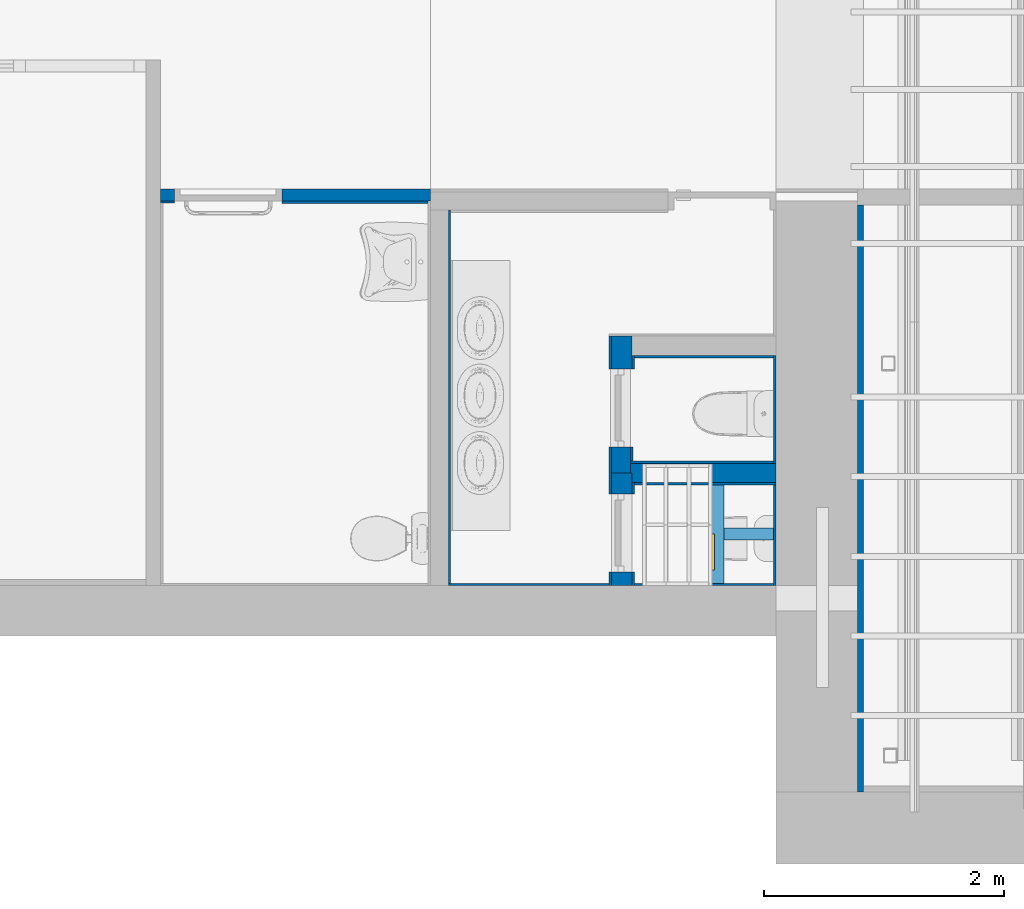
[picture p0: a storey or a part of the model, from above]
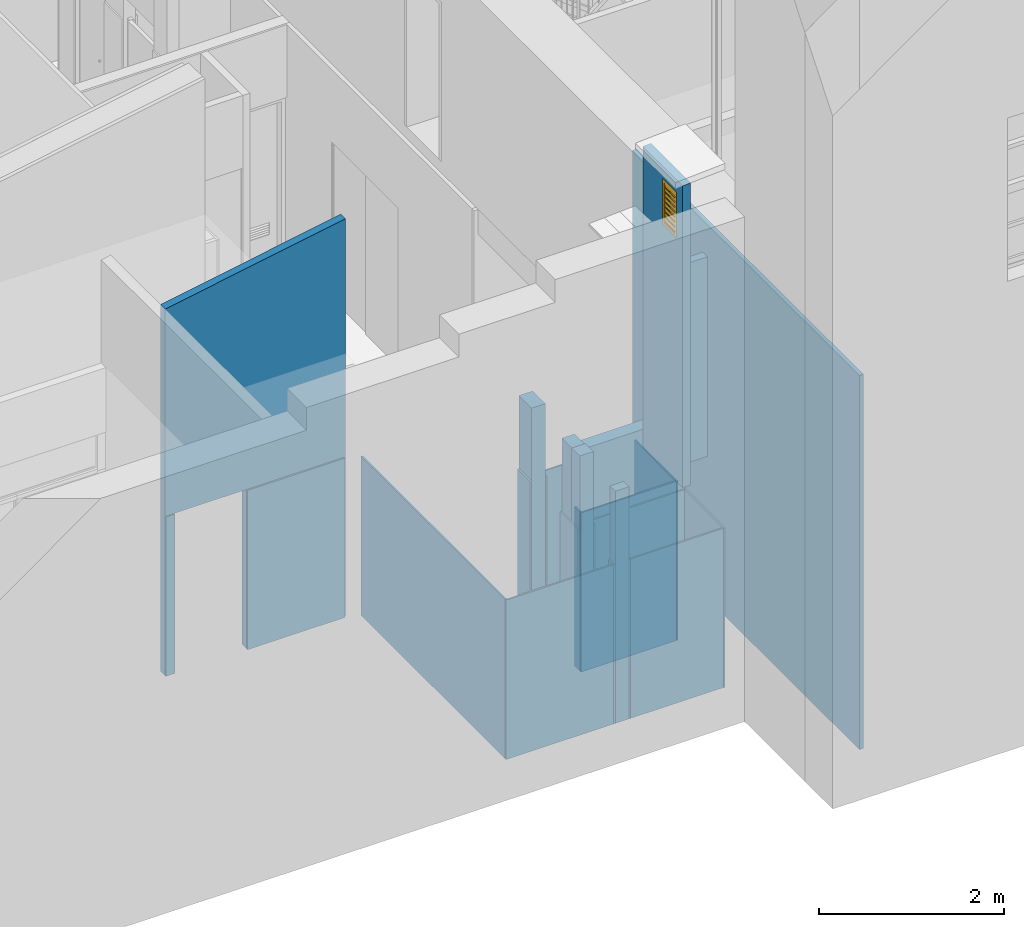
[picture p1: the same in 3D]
Properties of the parts of a building model (IFC2X3), part 1 of 2

# File
Description: ViewDefinition [CoordinationView_V2.0]
File name: 0001
Time: 2022-05-12T08:54:10
Written by: The EXPRESS Data Manager Version 5.02.0100.07 : 28 Aug 2013
Made in: 22.0.2.392 - Exporter 22.0.2.392 - IU alternativa 22.0.2.392
Comment: STEP Physical File produced by: The EXPRESS Data Manager Version 5.02.0100.07 : 28 Aug 2013 * Module: EDMstepFileFactory/EDMstandAlone * Creation date: Thu May 12 08:54:10 2022 * Host: DESKTOP-I1MM6I7 * Database: C:\Users\ALICIA~1\AppData\Local\Temp\2955ec9d-cea3-4671-8ac2-586a860548f9\22b83424-c5d4-4211-a013-65c01f56ca2a\ifc * Database version: 5507 * Database creation date: Thu May 12 08:53:25 2022 * Schema: IFC2X3 * Model: DataRepository.ifc * Model creation date: Thu May 12 08:53:25 2022 * Header model: DataRepository.ifc_HeaderModel * Header model creation date: Thu May 12 08:53:25 2022 * EDMuser: sdai-user * EDMgroup: sdai-group * License ID and type: 5605 : Permanent license. Expiry date: * EDMstepFileFactory options: 020000

# IfcProject, 0001
LongName: Nombre de proyecto; Phase: Estado de proyecto

# IfcSite, Superficie:1686468
RefLatitude: -34, -54, -17, -734680; RefLongitude: -56, -11, -31, -452026; RefElevation: 0 m

# IfcBuilding, Telegestiones
LongName: Telegestiones
Pset_AirSideSystemInformation - Description: LOCAL PARA TELEGESTIONES Local para Telegestiones - Centro
Pset_BuildingCommon - NumberOfStoreys: 4

# IfcBuildingStorey: Nivel:Extremo inicial Triangulo (4)
In: Telegestiones
Name | LongName | Elevation (m)
Nivel 0_NPT | Nivel 0_NPT | 0
Entrepiso_NPT | Entrepiso_NPT | 3.21
Nivel 1_NPT | Nivel 1_NPT | 4.94
Nivel 3_SUP | Nivel 3_SUP | 13.23

# IfcBeam: EST-PER-C-HGalv:C150X19.3 (10)
In: Nivel 0_NPT
Type - Pset_BeamCommon - IsExternal: no; LoadBearing: yes
Material: Metal - Acero - 345 MPa
Pset_BeamCommon - Slope: 0 deg; Reference: C150X19.3; Span: 19.49 m
Pset_QuantityTakeOff - Reference: C150X19.3; sets with these values: 2
Name (EST-PER-C-HGalv:C150X19.3:...)
1310847
1311190
1311201
1311212
1311223
1436319
1436321
1436323
1436325
1436327

# IfcBeam: EST-VI-PNI-Acero:EST-VI-IPN 140 (4)
In: Nivel 1_NPT
Type - Pset_BeamCommon - IsExternal: no; LoadBearing: yes
Material: Metal - Acero - 345 MPa
Pset_BeamCommon - Slope: 0 deg; Reference: EST-VI-IPN 140
Pset_QuantityTakeOff - Reference: EST-VI-IPN 140; sets with these values: 2
Name (EST-VI-PNI-Acero:EST-VI-IPN 140:...) | Span (m)
1302763 | 3.343
1389880 | 3.44
1452239 | 3.31
1452257 | 3.39

# IfcBeam: Hormigón-Viga rectangular:200x150 (2)
In: Entrepiso_NPT
Type - Pset_BeamCommon - IsExternal: no; LoadBearing: yes
Material: Hormigón, Moldeado in situ, gris
Pset_BeamCommon - Reference: 200x150; Span: 2.774 m; Slope: 10.384 deg
Pset_QuantityTakeOff - Reference: 200x150; sets with these values: 2
Name (Hormigón-Viga rectangular:200x150:...)
1787073
1787456

# IfcBeam: IPN - Secciones en I con alas cónicas:IPN 140 (2)
Type - PredefinedType: BEAM
Type - Pset_BeamCommon - IsExternal: no; LoadBearing: yes
Description: BP{BB9B63AE-4B4C-4E9F-9065-6A533A8D44FD}; Material: Metal - Acero - 345 MPa
Pset_BeamCommon - Slope: 0 deg; Reference: IPN 140
Pset_QuantityTakeOff - Reference: IPN 140; sets with these values: 2
ProfileProperties - SectionFamily: {BB9B63AE-4B4C-4E9F-9065-6A533A8D44FD}BP; Section: BP{BB9B63AE-4B4C-4E9F-9065-6A533A8D44FD}
Name (IPN - Secciones en I con alas cónicas:IPN 140:...) | In | Span (m)
1514774 | Nivel 0_NPT | 1.334
1530191 | Nivel 1_NPT | 1.253

# IfcBeam: IPN - Secciones en I con alas cónicas:IPN 140 (107)
Type - Pset_BeamCommon - IsExternal: no; LoadBearing: yes
Material: Metal - Acero - 345 MPa
Pset_BeamCommon - Reference: IPN 140
Pset_QuantityTakeOff - Reference: IPN 140; sets with these values: 2
Name (IPN - Secciones en I con alas cónicas:IPN 140:...) | In | Slope (deg) | Span (m)
1302759 | Nivel 1_NPT | 0 | 3.343
1302761 | Nivel 1_NPT | 0 | 3.49
1302765 | Nivel 1_NPT | 0 | 3.617
1302767 | Nivel 1_NPT | 0 | 3.617
1302769 | Nivel 1_NPT | 0 | 3.584
1387365 | Nivel 0_NPT | 0 | 0.7
1387483 | Nivel 1_NPT | 0 | 3.702
1388269 | Nivel 1_NPT | 0 | 3.586
1388583 | Nivel 1_NPT | 0 | 3.699
1389023 | Nivel 1_NPT | 0 | 3.699
1389478 | Nivel 1_NPT | 0 | 3.439
1391686 | Nivel 1_NPT | 0 | 3.69
1391717 | Nivel 1_NPT | 0 | 3.69
1391768 | Nivel 1_NPT | 0 | 3.69
1391782 | Nivel 1_NPT | 0 | 3.69
1391796 | Nivel 1_NPT | 0 | 3.69
1391810 | Nivel 1_NPT | 0 | 3.58
1391882 | Nivel 1_NPT | 0 | 3.58
1391896 | Nivel 1_NPT | 0 | 3.69
1391910 | Nivel 1_NPT | 0 | 3.69
1391924 | Nivel 1_NPT | 0 | 3.69
1391938 | Nivel 1_NPT | 0 | 3.69
1391952 | Nivel 1_NPT | 0 | 3.69
1392840 | Nivel 1_NPT | 0 | 3.48
1392855 | Nivel 1_NPT | 0 | 3.48
1392869 | Nivel 1_NPT | 0 | 3.48
1392887 | Nivel 1_NPT | 0 | 3.48
1392901 | Nivel 1_NPT | 0 | 3.48
1392915 | Nivel 1_NPT | 0 | 3.48
1392929 | Nivel 1_NPT | 0 | 3.48
1392943 | Nivel 1_NPT | 0 | 3.48
1392957 | Nivel 1_NPT | 0 | 3.48
1392971 | Nivel 1_NPT | 0 | 3.48
1392985 | Nivel 1_NPT | 0 | 3.48
1392999 | Nivel 1_NPT | 0 | 3.48
1452235 | Nivel 1_NPT | 0 | 3.31
1452237 | Nivel 1_NPT | 0 | 3.31
1452241 | Nivel 1_NPT | 0 | 3.31
1452243 | Nivel 1_NPT | 0 | 3.31
1452245 | Nivel 1_NPT | 0 | 3.31
1452247 | Nivel 1_NPT | 0 | 3.393
1452249 | Nivel 1_NPT | 0 | 3.39
1452251 | Nivel 1_NPT | 0 | 3.39
1452253 | Nivel 1_NPT | 0 | 3.39
1452255 | Nivel 1_NPT | 0 | 3.404
1452303 | Nivel 1_NPT | 0 | 3.39
1452305 | Nivel 1_NPT | 0 | 3.39
1452307 | Nivel 1_NPT | 0 | 3.39
1452309 | Nivel 1_NPT | 0 | 3.39
1452311 | Nivel 1_NPT | 0 | 3.39
1452313 | Nivel 1_NPT | 0 | 3.39
1452315 | Nivel 1_NPT | 0 | 3.39
1452317 | Nivel 1_NPT | 0 | 3.39
1452319 | Nivel 1_NPT | 0 | 3.39
1452321 | Nivel 1_NPT | 0 | 3.39
1452323 | Nivel 1_NPT | 0 | 3.39
1452325 | Nivel 1_NPT | 0 | 3.39
1452327 | Nivel 1_NPT | 0 | 3.31
1452329 | Nivel 1_NPT | 0 | 3.31
1452331 | Nivel 1_NPT | 0 | 3.31
1452333 | Nivel 1_NPT | 0 | 3.31
1452335 | Nivel 1_NPT | 0 | 3.31
1452337 | Nivel 1_NPT | 0 | 3.31
1452339 | Nivel 1_NPT | 0 | 3.31
1452341 | Nivel 1_NPT | 0 | 3.31
1452343 | Nivel 1_NPT | 0 | 3.31
1452345 | Nivel 1_NPT | 0 | 3.31
1452347 | Nivel 1_NPT | 0 | 3.31
1452349 | Nivel 1_NPT | 0 | 3.31
1466745 | Entrepiso_NPT | 0 | 1.26
1468459 | Entrepiso_NPT | 0 | 1.434
1469216 | Nivel 0_NPT | 0 | 1.334
1507818 | Nivel 0_NPT | 0 | 1.331
1514178 | Nivel 0_NPT | 37.3038 | 2.68
1514263 | Entrepiso_NPT | 0 | 1.218
1515129 | Entrepiso_NPT | 0 | 1.218
1515537 | Nivel 0_NPT | 0.0407811 | 1.217
1517027 | Nivel 0_NPT | 0.0000139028 | 1.218
1520294 | Entrepiso_NPT | 38.7536 | 2.65
1520296 | Entrepiso_NPT | 0 | 1.224
1520381 | Entrepiso_NPT | 0 | 1.42
1520383 | Entrepiso_NPT | 39.5917 | 2.593
1530181 | Nivel 1_NPT | 0 | 1.808
1567799 | Nivel 0_NPT | 0.00664997 | 1.334
1572878 | Nivel 1_NPT | 0 | 1.26
1572880 | Nivel 1_NPT | 0 | 1.334
1572882 | Nivel 1_NPT | 0 | 1.331
1572884 | Nivel 1_NPT | 35.1375 | 2.588
1572886 | Nivel 1_NPT | 0 | 1.218
1572888 | Nivel 1_NPT | 0.0515534 | 1.214
1572892 | Nivel 1_NPT | 0.0000139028 | 1.218
1572894 | Nivel 1_NPT | 36.6208 | 3.554
1572896 | Nivel 1_NPT | 0 | 1.224
1572898 | Nivel 1_NPT | 0 | 1.763
1572900 | Nivel 1_NPT | 37.8927 | 2.485
1572919 | Nivel 1_NPT | 0.00664997 | 1.334
1704734 | Nivel 1_NPT | 0 | 3.39
1704811 | Nivel 1_NPT | 0 | 3.39
1704841 | Nivel 1_NPT | 0 | 3.39
1704871 | Nivel 1_NPT | 0 | 3.39
1952851 | Nivel 1_NPT | 0.0000139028 | 1.218
1953647 | Nivel 0_NPT | 37.266 | 2.678
1954668 | Entrepiso_NPT | 39.5917 | 2.593
1955246 | Entrepiso_NPT | 38.7536 | 2.65
1955866 | Nivel 1_NPT | 35.1375 | 2.588
1956488 | Nivel 1_NPT | 36.6208 | 3.554
1956881 | Nivel 1_NPT | 37.8927 | 2.485

# IfcBeam: IPN - Secciones en I con alas cónicas:IPN 160 (14)
In: Nivel 3_SUP
Type - Pset_BeamCommon - IsExternal: no; LoadBearing: yes
Material: Metal - Acero - 345 MPa
Pset_BeamCommon - Reference: IPN 160
Pset_QuantityTakeOff - Reference: IPN 160; sets with these values: 2
Name (IPN - Secciones en I con alas cónicas:IPN 160:...) | Span (m) | Slope (deg)
1299421 | 19.549 | 0
1299466 | 19.607 | 0
1306593 | 8.92 | 0
1306595 | 4.777 | 29.4682
1432829 | 4.777 | 29.4682
1435526 | 8.92 | 0
1435528 | 4.777 | 29.4682
1435532 | 4.777 | 29.4682
1435557 | 8.92 | 0
1435559 | 4.777 | 29.4682
1435563 | 4.777 | 29.4682
1435588 | 8.92 | 0
1435590 | 4.777 | 29.4682
1435594 | 4.777 | 29.4682

# IfcBeam: IPN - Secciones en I con alas cónicas:IPN 200 (11)
In: Nivel 1_NPT
Type - Pset_BeamCommon - IsExternal: no; LoadBearing: yes
Material: Metal - Acero - 345 MPa
Pset_BeamCommon - Slope: 0 deg; Reference: IPN 200
Pset_QuantityTakeOff - Reference: IPN 200; sets with these values: 2
Name (IPN - Secciones en I con alas cónicas:IPN 200:...) | Span (m)
1302747 | 18.951
1302749 | 19.491
1302751 | 7.088
1302755 | 6.98
1302757 | 7.44
1386960 | 7.088
1452225 | 18.951
1452227 | 18.951
1452229 | 7.608
1452231 | 20.149
1452233 | 6.981

# IfcBeam: IPN - Secciones en I con alas cónicas:IPN 80 (94)
Type - Pset_BeamCommon - IsExternal: no; LoadBearing: yes
Material: Metal - Acero - 345 MPa
Pset_BeamCommon - Slope: 0 deg; Reference: IPN 80
Pset_QuantityTakeOff - Reference: IPN 80; sets with these values: 2
Name (IPN - Secciones en I con alas cónicas:IPN 80:...) | In | Span (m)
1390570 | Nivel 1_NPT | 1.616
1390802 | Nivel 1_NPT | 1.63
1390847 | Nivel 1_NPT | 1.63
1390906 | Nivel 1_NPT | 1.627
1391048 | Nivel 1_NPT | 1.616
1391101 | Nivel 1_NPT | 1.616
1391143 | Nivel 1_NPT | 1.63
1391172 | Nivel 1_NPT | 1.63
1391198 | Nivel 1_NPT | 1.63
1391265 | Nivel 1_NPT | 1.63
1391267 | Nivel 1_NPT | 1.63
1391269 | Nivel 1_NPT | 1.63
1391372 | Nivel 1_NPT | 1.63
1391374 | Nivel 1_NPT | 1.63
1391376 | Nivel 1_NPT | 1.63
1391414 | Nivel 1_NPT | 1.63
1391505 | Nivel 1_NPT | 1.63
1391507 | Nivel 1_NPT | 1.63
1391509 | Nivel 1_NPT | 1.63
1391581 | Nivel 1_NPT | 1.63
1391583 | Nivel 1_NPT | 1.63
1391585 | Nivel 1_NPT | 1.63
1452259 | Nivel 1_NPT | 1.616
1452261 | Nivel 1_NPT | 1.63
1452263 | Nivel 1_NPT | 1.63
1452265 | Nivel 1_NPT | 1.627
1452267 | Nivel 1_NPT | 1.63
1452269 | Nivel 1_NPT | 1.63
1452271 | Nivel 1_NPT | 1.63
1452273 | Nivel 1_NPT | 1.63
1452275 | Nivel 1_NPT | 1.63
1452277 | Nivel 1_NPT | 1.63
1452279 | Nivel 1_NPT | 1.63
1452281 | Nivel 1_NPT | 1.63
1452283 | Nivel 1_NPT | 1.63
1452285 | Nivel 1_NPT | 1.63
1452287 | Nivel 1_NPT | 1.63
1452289 | Nivel 1_NPT | 1.63
1452291 | Nivel 1_NPT | 1.63
1452293 | Nivel 1_NPT | 1.63
1452295 | Nivel 1_NPT | 1.63
1452297 | Nivel 1_NPT | 1.63
1452299 | Nivel 1_NPT | 1.63
1452301 | Nivel 1_NPT | 1.63
1880641 | Nivel 0_NPT | 3.86
1881168 | Nivel 0_NPT | 3.86
1881208 | Nivel 0_NPT | 3.86
1881211 | Nivel 0_NPT | 3.84
1881214 | Nivel 0_NPT | 3.86
1881288 | Nivel 0_NPT | 3.88
1881408 | Nivel 0_NPT | 3.86
1881443 | Nivel 0_NPT | 3.84
1881446 | Nivel 0_NPT | 3.86
1881449 | Nivel 0_NPT | 3.86
1881863 | Nivel 0_NPT | 4.44
1881866 | Nivel 0_NPT | 3.96
1881869 | Nivel 0_NPT | 3.955
1881872 | Nivel 0_NPT | 3.94
1881875 | Nivel 0_NPT | 3.96
1881878 | Nivel 0_NPT | 3.96
1881882 | Nivel 0_NPT | 3.96
1881885 | Nivel 0_NPT | 3.96
1881888 | Nivel 0_NPT | 3.96
1881891 | Nivel 0_NPT | 3.96
1882894 | Nivel 0_NPT | 3.902
1882897 | Nivel 0_NPT | 3.9
1882900 | Nivel 0_NPT | 3.907
1882903 | Nivel 0_NPT | 3.922
1882906 | Nivel 0_NPT | 3.902
1882909 | Nivel 0_NPT | 3.902
1882912 | Nivel 0_NPT | 3.902
1882915 | Nivel 0_NPT | 3.902
1882918 | Nivel 0_NPT | 3.902
1882921 | Nivel 0_NPT | 3.902
1882972 | Nivel 0_NPT | 4.097
1882975 | Nivel 0_NPT | 4.102
1882978 | Nivel 0_NPT | 4.1
1882981 | Nivel 0_NPT | 4.1
1882984 | Nivel 0_NPT | 4.1
1882987 | Nivel 0_NPT | 4.1
1882990 | Nivel 0_NPT | 4.1
1882993 | Nivel 0_NPT | 4.1
1882996 | Nivel 0_NPT | 4.1
1882999 | Nivel 0_NPT | 4.1
1883056 | Nivel 0_NPT | 4.095
1883059 | Nivel 0_NPT | 4.084
1883062 | Nivel 0_NPT | 4.084
1883065 | Nivel 0_NPT | 4.104
1883068 | Nivel 0_NPT | 4.084
1883071 | Nivel 0_NPT | 4.093
1883075 | Nivel 0_NPT | 4.084
1883078 | Nivel 0_NPT | 4.08
1883081 | Nivel 0_NPT | 4.084
1883084 | Nivel 0_NPT | 4.06

# IfcBeam: Madera:50x50mm (55)
Type - Pset_BeamCommon - IsExternal: no; LoadBearing: yes
Material: Madera - Madera de construcción
Pset_BeamCommon - Reference: 50x50mm
Pset_QuantityTakeOff - Reference: 50x50mm; sets with these values: 2
Name (Madera:50x50mm:...) | In | Span (m) | Slope (deg)
1884251 | Nivel 0_NPT | 5.14 | 29.4623
1884730 | Nivel 0_NPT | 5.14 | 29.4623
1884810 | Nivel 0_NPT | 5.14 | 29.4623
1884813 | Nivel 0_NPT | 5.14 | 29.4623
1884831 | Nivel 0_NPT | 5.14 | 29.4623
1884833 | Nivel 0_NPT | 5.14 | 29.4623
1884851 | Nivel 0_NPT | 5.14 | 29.4623
1884853 | Nivel 0_NPT | 5.14 | 29.4623
1884871 | Nivel 0_NPT | 5.14 | 29.4623
1884873 | Nivel 0_NPT | 5.14 | 29.4623
1885272 | Nivel 0_NPT | 5.14 | 29.4623
1885275 | Nivel 0_NPT | 5.14 | 29.4623
1885277 | Nivel 0_NPT | 5.14 | 29.4623
1885279 | Nivel 0_NPT | 5.14 | 29.4623
1885281 | Nivel 0_NPT | 5.14 | 29.4623
1885283 | Nivel 0_NPT | 5.14 | 29.4623
1885285 | Nivel 0_NPT | 5.14 | 29.4623
1885287 | Nivel 0_NPT | 5.14 | 29.4623
1885289 | Nivel 0_NPT | 5.14 | 29.4623
1885291 | Nivel 0_NPT | 5.14 | 29.4623
1885501 | Nivel 0_NPT | 5.14 | 29.4623
1885503 | Nivel 0_NPT | 5.14 | 29.4623
1885505 | Nivel 0_NPT | 5.14 | 29.4623
1885507 | Nivel 0_NPT | 5.14 | 29.4623
1885509 | Nivel 0_NPT | 5.14 | 29.4623
1885646 | Nivel 0_NPT | 5.14 | 29.4623
1885648 | Nivel 0_NPT | 5.14 | 29.4623
1885650 | Nivel 0_NPT | 5.14 | 29.4623
1885652 | Nivel 0_NPT | 5.14 | 29.4623
1885654 | Nivel 0_NPT | 5.14 | 29.4623
1885720 | Nivel 0_NPT | 5.14 | 29.4623
1885722 | Nivel 0_NPT | 5.14 | 29.4623
1885724 | Nivel 0_NPT | 5.14 | 29.4623
1885726 | Nivel 0_NPT | 5.14 | 29.4623
1885728 | Nivel 0_NPT | 5.14 | 29.4623
1885813 | Nivel 0_NPT | 5.14 | 29.4623
1885815 | Nivel 0_NPT | 5.14 | 29.4623
1885817 | Nivel 0_NPT | 5.14 | 29.4623
1885819 | Nivel 0_NPT | 5.14 | 29.4623
1885821 | Nivel 0_NPT | 5.14 | 29.4623
1885892 | Nivel 0_NPT | 5.14 | 29.4623
1885894 | Nivel 0_NPT | 5.14 | 29.4623
1885896 | Nivel 0_NPT | 5.14 | 29.4623
1885898 | Nivel 0_NPT | 5.14 | 29.4623
1885900 | Nivel 0_NPT | 5.14 | 29.4623
1885902 | Nivel 0_NPT | 5.14 | 29.4623
1885904 | Nivel 0_NPT | 5.14 | 29.4623
1885906 | Nivel 0_NPT | 5.14 | 29.4623
1885908 | Nivel 0_NPT | 5.14 | 29.4623
1885910 | Nivel 0_NPT | 5.14 | 29.4623
1886565 | Nivel 3_SUP | 3.955 | 0
1887055 | Nivel 3_SUP | 3.907 | 0
1887160 | Nivel 3_SUP | 3.888 | 0
1887330 | Nivel 3_SUP | 3.853 | 0
1887413 | Nivel 3_SUP | 4.113 | 0

# IfcBeam: U-Canales de ala paralela:UAP80 (10)
In: Nivel 0_NPT
Type - Pset_BeamCommon - IsExternal: no; LoadBearing: yes
Material: Metal - Acero - 345 MPa
Pset_BeamCommon - Slope: 0 deg; Reference: UAP80
Pset_QuantityTakeOff - Reference: UAP80; sets with these values: 2
Name (U-Canales de ala paralela:UAP80:...) | Span (m)
1764351 | 0.887
1766259 | 0.889
1766312 | 0.887
1766316 | 0.919
1766320 | 0.889
1766324 | 0.89
1766328 | 0.889
1766332 | 0.889
1766336 | 0.889
1773133 | 0.889

# IfcBeam: U-Canales de ala paralela:UPE160 (2)
In: Nivel 0_NPT
Type - Pset_BeamCommon - IsExternal: no; LoadBearing: yes
Material: Metal - Acero - 345 MPa
Pset_BeamCommon - Slope: 0 deg; Reference: UPE160
Pset_QuantityTakeOff - Reference: UPE160; sets with these values: 2
Name (U-Canales de ala paralela:UPE160:...) | Span (m)
1763657 | 9.61 | Pset_BeamCommon - IsExternal: yes
1763941 | 9.62

# IfcBuildingElementProxy: ARQ-ALE-EXT:Tipo 1, ARQ-ALE-EXT:Tipo 1:1745585
In: Entrepiso_NPT
Type - Material: <Unnamed>, Vidrio
Pset_BuildingElementProxyCommon - Reference: Tipo 1; sets with these values: 2

# IfcBuildingElementProxy: ARQ-BAR- Pasarela cubierta 2:ARQ-BAR- Pasarela cubierta 2, ARQ-BAR- Pasarela cubierta 2:ARQ-BAR- Pasarela cubierta 2:1774991
In: Nivel 3_SUP
Type - Material: <Unnamed> (16)
Pset_BuildingElementProxyCommon - Reference: ARQ-BAR- Pasarela cubierta 2; sets with these values: 2
Pset_ProvisionForVoid - Width: 8.81 m; Height: 0.05 m; Depth: 8.81 m

# IfcBuildingElementProxy: ARQ-BAR- Pasarela cubierta:ARQ-BAR- Pasarela cubierta, ARQ-BAR- Pasarela cubierta:ARQ-BAR- Pasarela cubierta:1775362
In: Nivel 3_SUP
Type - Material: <Unnamed> (16)
Pset_BuildingElementProxyCommon - Reference: ARQ-BAR- Pasarela cubierta; sets with these values: 2
Pset_ProvisionForVoid - Width: 9.61 m; Height: 0.05 m; Depth: 9.61 m

# IfcBuildingElementProxy: ARQ-ESC-EX-Ace-H3:Tipo 1 (2)
In: Nivel 3_SUP
Type - Material: <Unnamed>
Pset_BuildingElementProxyCommon - Reference: Tipo 1; sets with these values: 2
Name (ARQ-ESC-EX-Ace-H3:Tipo 1:...)
1776751
1776914

# IfcBuildingElementProxy: ARQ-ESC-EX-Ace:ARQ-ESC-EX-Ace, ARQ-ESC-EX-Ace:ARQ-ESC-EX-Ace:1759845
In: Nivel 1_NPT
Type - Material: <Unnamed>
Pset_BuildingElementProxyCommon - Reference: ARQ-ESC-EX-Ace; sets with these values: 2

# IfcBuildingElementProxy: ARQ-MU-EXT-Lad:Tipo 1 (12)
Type - Material: Albañilería expuesta (2)
Pset_BuildingElementProxyCommon - Reference: Tipo 1; sets with these values: 2
Pset_ProvisionForVoid - Height: 0.7 m
Name (ARQ-MU-EXT-Lad:Tipo 1:...) | In | Width (m) = Depth (m) | Material
1489611 | Nivel 3_SUP | 10.88
1491020 | Nivel 1_NPT | 10.88 | Albañilería expuesta
1491091 | Nivel 1_NPT | 10.88 | Albañilería expuesta
1491114 | Nivel 1_NPT | 10.88 | Albañilería expuesta
1491135 | Nivel 1_NPT | 10.88 | Albañilería expuesta
1491181 | Nivel 3_SUP | 10.88 | Albañilería expuesta
1492168 | Nivel 1_NPT | 9.7
1492191 | Nivel 1_NPT | 9.7 | Albañilería expuesta
1493948 | Nivel 3_SUP | 9.7 | Albañilería expuesta
1494081 | Nivel 1_NPT | 9.7 | Albañilería expuesta
1494138 | Nivel 1_NPT | 9.7 | Albañilería expuesta
1494168 | Nivel 1_NPT | 9.7 | Albañilería expuesta

# IfcBuildingElementProxy: ARQ-PAS-Osogrid-Ace:ARQ-PAS-Osogrid-Ace, ARQ-PAS-Osogrid-Ace:ARQ-PAS-Osogrid-Ace:1771462
In: Nivel 0_NPT
Type - Material: <Unnamed> (130)
Pset_BuildingElementProxyCommon - Reference: ARQ-PAS-Osogrid-Ace; sets with these values: 2
Pset_ProvisionForVoid - Width: 0.035 m; Height: 0.0025 m; Depth: 0.035 m

# IfcBuildingElementProxy: ARQ-Plataforma-Ace:ARQ-Plataforma-Ace, ARQ-Plataforma-Ace:ARQ-Plataforma-Ace:1753381
In: Nivel 1_NPT
Type - Material: <Unnamed>
Pset_BuildingElementProxyCommon - Reference: ARQ-Plataforma-Ace; sets with these values: 2

# IfcBuildingElementProxy: Armazón estructural 10:Armazón estructural 10, Armazón estructural 10:Armazón estructural 10:1543469
In: Entrepiso_NPT
Type - Material: Acero (10)
Pset_BuildingElementProxyCommon - Reference: Armazón estructural 10; sets with these values: 2
Pset_ProvisionForVoid - Width: 11.68 m; Depth: 11.68 m

# IfcBuildingElementProxy: Armazón estructural 1:Armazón estructural 1, Armazón estructural 1:Armazón estructural 1:1521064
In: Nivel 0_NPT
Type - Material: Metal-Acero
Pset_BuildingElementProxyCommon - Reference: Armazón estructural 1; sets with these values: 2
Pset_ProvisionForVoid - Width: 0.0564877 m; Height: 1.28479 m; Depth: 0.0564877 m

# IfcBuildingElementProxy: Armazón estructural 2:Armazón estructural 1, Armazón estructural 2:Armazón estructural 1:1572918
In: Nivel 1_NPT
Type - Material: Metal-Acero
Pset_BuildingElementProxyCommon - Reference: Armazón estructural 1; sets with these values: 2
Pset_ProvisionForVoid - Width: 0.0564877 m; Height: 1.28479 m; Depth: 0.0564877 m

# IfcBuildingElementProxy: Armazón estructural 5:Armazón estructural 3, Armazón estructural 5:Armazón estructural 3:1538624
In: Nivel 0_NPT
Type - Material: 391846a9_3117_44ae_832e_53e94a79c5b7 (2)
Pset_BuildingElementProxyCommon - Reference: Armazón estructural 3; sets with these values: 2
Pset_ProvisionForVoid - Width: 0.03 m; Depth: 0.03 m

# IfcBuildingElementProxy: Armazón estructural 6:Armazón estructural 3, Armazón estructural 6:Armazón estructural 3:1942421
In: Nivel 1_NPT
Type - Material: 391846a9_3117_44ae_832e_53e94a79c5b7 (4)
Pset_BuildingElementProxyCommon - Reference: Armazón estructural 3; sets with these values: 2
Pset_ProvisionForVoid - Width: 0.03 m; Depth: 0.03 m

# IfcBuildingElementProxy: Armazón estructural 7:Armazón estructural 7, Armazón estructural 7:Armazón estructural 7:1540061
In: Entrepiso_NPT
Type - Material: 391846a9_3117_44ae_832e_53e94a79c5b7 (2)
Pset_BuildingElementProxyCommon - Reference: Armazón estructural 7; sets with these values: 2
Pset_ProvisionForVoid - Width: 0.03 m; Depth: 0.03 m

# IfcBuildingElementProxy: Armazón estructural 8:Armazón estructural 7, Armazón estructural 8:Armazón estructural 7:1946343
In: Nivel 1_NPT
Type - Material: 391846a9_3117_44ae_832e_53e94a79c5b7 (2)
Pset_BuildingElementProxyCommon - Reference: Armazón estructural 7; sets with these values: 2
Pset_ProvisionForVoid - Width: 0.03 m; Depth: 0.03 m

# IfcBuildingElementProxy: Busto de Artigas:Busto de Artigas, Busto de Artigas:Busto de Artigas:1333514
In: Nivel 0_NPT
Type - Material: Hormigón, C12/15 (2)
Pset_BuildingElementProxyCommon - Reference: Busto de Artigas; sets with these values: 2
Pset_ProvisionForVoid - Width: 1.2 m; Height: 0.39 m; Depth: 1.2 m

# IfcBuildingElementProxy: Busto:Busto, Busto:Busto:1826441
In: Nivel 0_NPT
Type - Material: Acero (2)
Pset_BuildingElementProxyCommon - Reference: Busto; sets with these values: 2
Pset_ProvisionForVoid - Width: 0.05 m; Depth: 0.05 m

# IfcBuildingElementProxy: EST-PERF-Ace:EST-PERF-Ace (32)
In: Nivel 1_NPT
Type - Material: Metal-Acero
Pset_BuildingElementProxyCommon - Reference: EST-PERF-Ace; sets with these values: 2
Pset_ProvisionForVoid - Width: 0.01 m; Depth: 0.01 m
Name (EST-PERF-Ace:EST-PERF-Ace:...)
1717569
1718236
1718275
1718317
1718358
1718379
1718398
1718419
1718788
1718807
1718826
1718847
1718866
1718885
1718904
1718923
1718949
1721362
1721381
1721400
1721419
1721438
1721457
1721476
1721495
1721514
1721533
1721552
1721575
1721594
1721613
1721632

# IfcBuildingElementProxy: Perfiles escalera1:Perfiles escalera, Perfiles escalera1:Perfiles escalera:1573338
In: Nivel 1_NPT
Type - Material: Acero (2)
Pset_BuildingElementProxyCommon - Reference: Perfiles escalera; sets with these values: 2
Pset_ProvisionForVoid - Width: 0.03 m; Depth: 0.03 m

# IfcBuildingElementProxy: Perfiles escalera2:Perfiles escalera, Perfiles escalera2:Perfiles escalera:1957731
In: Nivel 0_NPT
Type - Material: Acero
Pset_BuildingElementProxyCommon - Reference: Perfiles escalera; sets with these values: 2
Pset_ProvisionForVoid - Width: 0.03 m; Depth: 0.03 m

# IfcBuildingElementProxy: Perfiles escalera:Perfiles escalera, Perfiles escalera:Perfiles escalera:1534310
In: Nivel 0_NPT
Type - Material: Acero
Pset_BuildingElementProxyCommon - Reference: Perfiles escalera; sets with these values: 2
Pset_ProvisionForVoid - Width: 0.03 m; Depth: 0.03 m

# IfcBuildingElementProxy: RPC Árbol - Otoño:Abedul gris - 3,1 metros (4)
In: Nivel 0_NPT
Type - Material: <Unnamed>
Pset_BuildingElementProxyCommon - Reference: Abedul gris - 3,1 metros; sets with these values: 2
Name (RPC Árbol - Otoño:Abedul gris - 3,1 metros:...)
1856726
1856905
1856915
1856923

# IfcBuildingElementProxy: RPC Árbol - Otoño:Acacia de tres púas - 7,6 metros, RPC Árbol - Otoño:Acacia de tres púas - 7,6 metros:1856717
In: Nivel 0_NPT
Type - Material: <Unnamed>
Pset_BuildingElementProxyCommon - Reference: Acacia de tres púas - 7,6 metros; sets with these values: 2

# IfcBuildingElementProxy: RPC Árbol - Otoño:Fresno blanco - 9,1 metros, RPC Árbol - Otoño:Fresno blanco - 9,1 metros:1829723
In: Nivel 0_NPT
Type - Material: <Unnamed>
Pset_BuildingElementProxyCommon - Reference: Fresno blanco - 9,1 metros; sets with these values: 2

# IfcBuildingElementProxy: RPC Árbol - Otoño:Haya americana - 6,0 metros, RPC Árbol - Otoño:Haya americana - 6,0 metros:1856966
In: Nivel 0_NPT
Type - Material: <Unnamed>
Pset_BuildingElementProxyCommon - Reference: Haya americana - 6,0 metros; sets with these values: 2

# IfcBuildingElementProxy: RPC Árbol - Otoño:Roble de Shumard - 12,2 metros, RPC Árbol - Otoño:Roble de Shumard - 12,2 metros:1856706
In: Nivel 0_NPT
Type - Material: <Unnamed>
Pset_BuildingElementProxyCommon - Reference: Roble de Shumard - 12,2 metros; sets with these values: 2

# IfcBuildingElementProxy: Tapas Canalon:Tapas Canalon, Tapas Canalon:Tapas Canalon:1939655
In: Nivel 0_NPT
Type - Material: Acero (4)
Pset_BuildingElementProxyCommon - Reference: Tapas Canalon; sets with these values: 2
Pset_ProvisionForVoid - Width: 0.141425 m; Height: 0.15095 m; Depth: 0.141425 m

# IfcColumn: SHS-Sección hueca cuadrada-Pilar:120 x 120SHS, SHS-Sección hueca cuadrada-Pilar:120 x 120SHS:1296653
In: Nivel 1_NPT
Type - PredefinedType: COLUMN; Material: Metal - Acero - 345 MPa
Type - Pset_ColumnCommon - IsExternal: no; LoadBearing: yes
Pset_ColumnCommon - Reference: 120 x 120SHS
Pset_QuantityTakeOff - Reference: 120 x 120SHS; sets with these values: 2

# IfcColumn: UPE - Canales de ala paralela - Pilar:UPE 120 (50)
Type - PredefinedType: COLUMN; Material: Metal - Acero - 345 MPa
Type - Pset_ColumnCommon - IsExternal: no; LoadBearing: yes
Pset_ColumnCommon - Reference: UPE 120
Pset_QuantityTakeOff - Reference: UPE 120; sets with these values: 2
Name (UPE - Canales de ala paralela - Pilar:UPE 120:...) | In
1295354 | Nivel 0_NPT
1296190 | Nivel 0_NPT
1296393 | Nivel 0_NPT
1296470 | Nivel 0_NPT
1296535 | Nivel 0_NPT
1296589 | Nivel 0_NPT
1296655 | Nivel 0_NPT
1297731 | Nivel 0_NPT
1298502 | Nivel 0_NPT
1298552 | Nivel 0_NPT
1298554 | Nivel 0_NPT
1298666 | Nivel 0_NPT
1298750 | Nivel 0_NPT
1298817 | Nivel 0_NPT
1298850 | Nivel 0_NPT
1298885 | Nivel 0_NPT
1298887 | Nivel 0_NPT
1298944 | Nivel 0_NPT
1298946 | Nivel 0_NPT
1298966 | Nivel 0_NPT
1298968 | Nivel 0_NPT
1298990 | Nivel 0_NPT
1298992 | Nivel 0_NPT
1579304 | Nivel 0_NPT
1579353 | Nivel 0_NPT
1579480 | Nivel 0_NPT
1579507 | Nivel 0_NPT
1579534 | Nivel 0_NPT
1579569 | Nivel 0_NPT
1579596 | Nivel 0_NPT
1579632 | Nivel 0_NPT
1579680 | Nivel 0_NPT
1579795 | Nivel 0_NPT
1579860 | Nivel 0_NPT
1580046 | Nivel 0_NPT
1580106 | Nivel 0_NPT
1580242 | Nivel 0_NPT
1580285 | Nivel 0_NPT
1580341 | Nivel 0_NPT
1580383 | Nivel 0_NPT
1580409 | Nivel 0_NPT
1580612 | Nivel 0_NPT
1580638 | Nivel 0_NPT
1580668 | Nivel 0_NPT
1580698 | Nivel 0_NPT
1580748 | Nivel 0_NPT
1580811 | Nivel 0_NPT
1580876 | Nivel 0_NPT
1767437 | Nivel 3_SUP
1767867 | Nivel 3_SUP

# IfcColumn: UPE - Canales de ala paralela - Pilar:UPE 80 (2)
In: Nivel 0_NPT
Type - PredefinedType: COLUMN; Material: Metal - Acero - 345 MPa
Type - Pset_ColumnCommon - IsExternal: no; LoadBearing: yes
Pset_ColumnCommon - Reference: UPE 80
Pset_QuantityTakeOff - Reference: UPE 80; sets with these values: 2
Name (UPE - Canales de ala paralela - Pilar:UPE 80:...)
1531447
1579977

# IfcCovering: Cielo raso de cubierta:ARQ-CL-IN-12-Ye (7)
In: Nivel 0_NPT
Type - PredefinedType: CEILING
Type - Pset_CoveringCommon - TotalThickness: 0.012 m
Material: Placa yeso entera 0.012 m
Pset_CoveringCommon - Reference: ARQ-CL-IN-12-Ye
Pset_QuantityTakeOff - Reference: ARQ-CL-IN-12-Ye
Name (Cielo raso de cubierta:ARQ-CL-IN-12-Ye:...)
1462650
1462922
1611340
1833401
1917778
1918066
1932960

# IfcCovering: Cielo raso de cubierta:ARQ-CL-IN-22-Ye + Aisl, Cielo raso de cubierta:ARQ-CL-IN-22-Ye + Aisl:1915491
In: Nivel 0_NPT
Type - PredefinedType: CEILING
Type - Pset_CoveringCommon - TotalThickness: 0.112 m
Material: Lana de roca 0.1 m, Placa yeso entera 0.012 m
Pset_CoveringCommon - Reference: ARQ-CL-IN-22-Ye + Aisl
Pset_QuantityTakeOff - Reference: ARQ-CL-IN-22-Ye + Aisl

# IfcCovering: Techo compuesto:ARQ-CL-Mad-Eucaliptus (2)
In: Nivel 3_SUP
Type - PredefinedType: CEILING
Type - Pset_CoveringCommon - TotalThickness: 0.013 m
Material: Roble, blanco 0.013 m
Pset_CoveringCommon - Reference: ARQ-CL-Mad-Eucaliptus
Pset_QuantityTakeOff - Reference: ARQ-CL-Mad-Eucaliptus
Name (Techo compuesto:ARQ-CL-Mad-Eucaliptus:...)
1893118
1964498

# IfcCurtainWall: Muro cortina:ARQ-MC-EX-Mampara M4, Muro cortina:ARQ-MC-EX-Mampara M4:1632516
In: Nivel 0_NPT
Type - Pset_CurtainWallCommon - IsExternal: yes
Pset_CurtainWallCommon - Reference: ARQ-MC-EX-Mampara M4
Pset_QuantityTakeOff - Reference: ARQ-MC-EX-Mampara M4

# IfcCurtainWall: Muro cortina:ARQ-MC-IN-Mampara Ma1, Muro cortina:ARQ-MC-IN-Mampara Ma1:1648648
In: Nivel 0_NPT
Type - Pset_CurtainWallCommon - IsExternal: no
Pset_CurtainWallCommon - Reference: ARQ-MC-IN-Mampara Ma1
Pset_QuantityTakeOff - Reference: ARQ-MC-IN-Mampara Ma1

# IfcCurtainWall: Muro cortina:ARQ-MC-IN-Mampara Ma2, Muro cortina:ARQ-MC-IN-Mampara Ma2:1647681
In: Nivel 0_NPT
Type - Pset_CurtainWallCommon - IsExternal: no
Pset_CurtainWallCommon - Reference: ARQ-MC-IN-Mampara Ma2
Pset_QuantityTakeOff - Reference: ARQ-MC-IN-Mampara Ma2

# IfcCurtainWall: Muro cortina:ARQ-MC-IN-Mampara Ma3, Muro cortina:ARQ-MC-IN-Mampara Ma3:1646348
In: Nivel 0_NPT
Type - Pset_CurtainWallCommon - IsExternal: no
Pset_CurtainWallCommon - Reference: ARQ-MC-IN-Mampara Ma3
Pset_QuantityTakeOff - Reference: ARQ-MC-IN-Mampara Ma3

# IfcCurtainWall: Muro cortina:ARQ-MC-IN-Mampara Ma4, Muro cortina:ARQ-MC-IN-Mampara Ma4:1644026
In: Nivel 0_NPT
Type - Pset_CurtainWallCommon - IsExternal: no
Pset_CurtainWallCommon - Reference: ARQ-MC-IN-Mampara Ma4
Pset_QuantityTakeOff - Reference: ARQ-MC-IN-Mampara Ma4

# IfcCurtainWall: Muro cortina:ARQ-MC-IN-Mampara Ma5, Muro cortina:ARQ-MC-IN-Mampara Ma5:1639143
In: Nivel 0_NPT
Type - Pset_CurtainWallCommon - IsExternal: no
Pset_CurtainWallCommon - Reference: ARQ-MC-IN-Mampara Ma5
Pset_QuantityTakeOff - Reference: ARQ-MC-IN-Mampara Ma5

# IfcCurtainWall: Muro cortina:ARQ-MC-IN-Mampara sshh angular (5)
In: Nivel 0_NPT
Type - Pset_CurtainWallCommon - IsExternal: yes
Pset_CurtainWallCommon - Reference: ARQ-MC-IN-Mampara sshh angular
Pset_QuantityTakeOff - Reference: ARQ-MC-IN-Mampara sshh angular
Name (Muro cortina:ARQ-MC-IN-Mampara sshh angular:...)
1817917
1818640
1818674
1818691
1926013

# IfcDistributionPort (24)
Description: Flow
Name | FlowDirection
2 x Port_1712261 | SOURCEANDSINK | Group: Agua fría sanitaria 1
2 x Port_1712467 | SOURCEANDSINK | Group: Agua fría sanitaria 2
Port_1817335 | SINK
Port_1817335 | SOURCE
Port_1817550 | SOURCE
Port_1817550 | SINK
Port_1817782 | SINK
Port_1817782 | SOURCE
Port_1817849 | SINK
Port_1817849 | SOURCE
Port_1820061 | SOURCE
Port_1820061 | SINK
Port_1901610 | SINK
Port_1901740 | SINK
Port_1901749 | SINK
Port_1906233 | SINK
Port_1906282 | SINK
Port_1906331 | SINK
Port_1913234 | SINK
Port_1925662 | SINK
2 x Port_1925662 | SOURCE

# IfcDoor: ARQ-MAM-EX-490x350-Vid:ARQ-MAM-EX-490x350-Vid, ARQ-MAM-EX-490x350-Vid:ARQ-MAM-EX-490x350-Vid:1363135
In: Nivel 0_NPT
Type - ParameterTakesPrecedence: no; Sizeable: no; Material: Aluminio (1) (24), Vidrio (5)
Type - Pset_DoorCommon - IsExternal: no
OverallHeight: 3.55 m; OverallWidth: 4.9 m
Pset_DoorCommon - Reference: ARQ-MAM-EX-490x350-Vid
Pset_QuantityTakeOff - Reference: ARQ-MAM-EX-490x350-Vid

# IfcDoor: ARQ-PU-EX-181x260-Alu-A3:ARQ-PU-EX-181x260-Alu-A3, ARQ-PU-EX-181x260-Alu-A3:ARQ-PU-EX-181x260-Alu-A3:1625602
In: Nivel 0_NPT
Type - ParameterTakesPrecedence: no; Sizeable: no; Material: Aluminio (8), Vidrio (4), <Unnamed>
Type - Pset_DoorCommon - IsExternal: no
OverallHeight: 2.6 m; OverallWidth: 1.9 m
Pset_DoorCommon - Reference: ARQ-PU-EX-181x260-Alu-A3
Pset_QuantityTakeOff - Reference: ARQ-PU-EX-181x260-Alu-A3

# IfcDoor: ARQ-PU-EX-80X260-Alu-A2:ARQ-PU-EX-80X260-Alu-A2, ARQ-PU-EX-80X260-Alu-A2:ARQ-PU-EX-80X260-Alu-A2:1622680
In: Nivel 0_NPT
Type - ParameterTakesPrecedence: no; Sizeable: no; Material: Aluminio (6), Vidrio (2), <Unnamed>
Type - Pset_DoorCommon - IsExternal: no
OverallHeight: 2.6 m; OverallWidth: 1 m
Pset_DoorCommon - Reference: ARQ-PU-EX-80X260-Alu-A2
Pset_QuantityTakeOff - Reference: ARQ-PU-EX-80X260-Alu-A2

# IfcDoor: ARQ-PU-IN-Barra accesible:210x90 cm, ARQ-PU-IN-Barra accesible:210x90 cm:1809539
In: Nivel 0_NPT
Type - OperationType: DOUBLE_SWING_LEFT; ParameterTakesPrecedence: no; Sizeable: no; Material: Caoba
Type - ARQ-PU-IN-Barra accesible:210x90 cm:1809539:1 - PanelOperation: DOUBLE_ACTING
Type - Pset_DoorCommon - IsExternal: no
OverallHeight: 2.1 m; OverallWidth: 0.9 m; Material: Caoba, Acero, acabado de pintura, rojo, Aluminio
Pset_DoorCommon - Reference: 210x90 cm
Pset_QuantityTakeOff - Reference: 210x90 cm

# IfcDoor: ARQ-PU-INT-90x210-Mad-C2:ARQ-PU-INT-65x210-Mad, ARQ-PU-INT-90x210-Mad-C2:ARQ-PU-INT-65x210-Mad:1662910
In: Nivel 0_NPT
Type - OperationType: DOUBLE_SWING_RIGHT; ParameterTakesPrecedence: no; Sizeable: no; Material: Caoba (2), Aluminio (6), <Unnamed> (2)
Type - ARQ-PU-INT-90x210-Mad-C2:ARQ-PU-INT-65x210-Mad:1662910:1 - PanelOperation: DOUBLE_ACTING
Type - Pset_DoorCommon - IsExternal: no
OverallHeight: 2.1 m; OverallWidth: 0.65 m
Pset_DoorCommon - Reference: ARQ-PU-INT-65x210-Mad
Pset_QuantityTakeOff - Reference: ARQ-PU-INT-65x210-Mad

# IfcDoor: ARQ-PU-INT-90x210-Mad-C3:ARQ-PU-INT-80x210-Mad, ARQ-PU-INT-90x210-Mad-C3:ARQ-PU-INT-80x210-Mad:1253737
In: Entrepiso_NPT
Type - OperationType: DOUBLE_SWING_RIGHT; ParameterTakesPrecedence: no; Sizeable: no; Material: Caoba (2), Aluminio (6), <Unnamed> (2)
Type - ARQ-PU-INT-90x210-Mad-C3:ARQ-PU-INT-80x210-Mad:1253737:1 - PanelOperation: DOUBLE_ACTING
Type - Pset_DoorCommon - IsExternal: no
OverallHeight: 2.1 m; OverallWidth: 0.8 m
Pset_DoorCommon - Reference: ARQ-PU-INT-80x210-Mad
Pset_QuantityTakeOff - Reference: ARQ-PU-INT-80x210-Mad

# IfcDoor: ARQ-PU-INT-90x210-Mad-C3:ARQ-PU-INT-90x210-Mad (2)
In: Nivel 0_NPT
Type - OperationType: DOUBLE_SWING_LEFT; ParameterTakesPrecedence: no; Sizeable: no; Material: Caoba (2), Aluminio (6), <Unnamed> (2)
Type - ARQ-PU-INT-90x210-Mad-C3:ARQ-PU-INT-90x210-Mad:1656004:1 - PanelOperation: DOUBLE_ACTING
Type - Pset_DoorCommon - IsExternal: no
OverallHeight: 2.1 m; OverallWidth: 0.9 m
Pset_DoorCommon - Reference: ARQ-PU-INT-90x210-Mad
Pset_QuantityTakeOff - Reference: ARQ-PU-INT-90x210-Mad
Name (ARQ-PU-INT-90x210-Mad-C3:ARQ-PU-INT-90x210-Mad:...)
1656004
1661131 | Material: Caoba, Aluminio, <Unnamed>

# IfcDoor: ARQ-PU-INT-90x210-Mad-C3:ARQ-PU-INT-95x210-Mad, ARQ-PU-INT-90x210-Mad-C3:ARQ-PU-INT-95x210-Mad:1936734
In: Entrepiso_NPT
Type - OperationType: DOUBLE_SWING_LEFT; ParameterTakesPrecedence: no; Sizeable: no; Material: Caoba (2), Aluminio (6), <Unnamed> (2)
Type - ARQ-PU-INT-90x210-Mad-C3:ARQ-PU-INT-95x210-Mad:1936734:1 - PanelOperation: DOUBLE_ACTING
Type - Pset_DoorCommon - IsExternal: no
OverallHeight: 2.1 m; OverallWidth: 1.05 m
Pset_DoorCommon - Reference: ARQ-PU-INT-95x210-Mad
Pset_QuantityTakeOff - Reference: ARQ-PU-INT-95x210-Mad

# IfcDoor: ARQ-PU-INT-Alu (muro cortina):ARQ-PU-IN-Alu-sshh (4)
In: Nivel 0_NPT
Type - ParameterTakesPrecedence: no; Sizeable: no; Material: Metal - Aluminio (2), <Unnamed>
Type - Pset_DoorCommon - IsExternal: no; ThermalTransmittance: 5.5617 kg/K/s3
OverallHeight: 1.78 m
Pset_DoorCommon - Reference: ARQ-PU-IN-Alu-sshh
Pset_QuantityTakeOff - Reference: ARQ-PU-IN-Alu-sshh
Name (ARQ-PU-INT-Alu (muro cortina):ARQ-PU-IN-Alu-sshh:...) | OverallWidth (m)
1817927 | 0.55
1818645 | 0.549973
1818679 | 0.559636
1818696 | 0.55

# IfcElementAssembly: EST-CER-Hi:Estándar (4)
In: Nivel 3_SUP
PredefinedType: TRUSS
Pset_QuantityTakeOff - Reference: Estándar
Name (EST-CER-Hi:Estándar:...)
1306582
1435525
1435556
1435587

# IfcFlowSegment: Canalón:ARQ-CAN-EXT-20x30-Hi:1879874 (2)
In: Nivel 3_SUP
Type - ElementType: Canalón:ARQ-CAN-EXT-20x30-Hi:1879874; PredefinedType: GUTTER
Pset_DistributionFlowElementCommon - Reference: ARQ-CAN-EXT-20x30-Hi; sets with these values: 2
Pset_FlowSegmentDuctSegment - Length: 19.55 m; sets with these values: 2
Pset_PipeSegmentTypeGutter - Slope: 0 deg
Name (Canalón:ARQ-CAN-EXT-20x30-Hi:...)
1416522
1436338 | Pset_PipeSegmentTypeGutter - sets with these values: 2

# IfcFlowSegment: Canalón:Canalón:19886 (2)
Type - ElementType: Canalón:Canalón:19886; PredefinedType: GUTTER
Pset_DistributionFlowElementCommon - Reference: Canalón; sets with these values: 2
Pset_FlowSegmentDuctSegment - sets with these values: 2
Pset_PipeSegmentTypeGutter - Slope: 0 deg; sets with these values: 2
Name (Canalón:Canalón:...) | In | Length (m)
1690987 | Entrepiso_NPT | 14.5519
1691568 | Nivel 0_NPT | 3.16

# IfcFlowSegment: Tipos de tubería:Por defecto (2)
In: Nivel 0_NPT
Pset_DistributionFlowElementCommon - Reference: Por defecto; sets with these values: 2
Pset_FlowSegmentDuctSegment - sets with these values: 2
Pset_PipeSegmentTypeGutter - Slope: 0 deg
Name (Tipos de tubería:Por defecto:...) | Length (m) | Group
1712261 | 4.1 | Agua fría sanitaria 1
1712467 | 2.7 | Agua fría sanitaria 2

# IfcFlowTerminal: ARQ-RE-EX-Ace:L=1.36m, ARQ-RE-EX-Ace:L=1.36m:1708023
In: Nivel 0_NPT
Type - Material: Acero (22)
Pset_DistributionFlowElementCommon - Reference: L=1.36m; sets with these values: 2

# IfcFlowTerminal: ARQ-RE-EX-Ace:L=2.51m, ARQ-RE-EX-Ace:L=2.51m:1708236
In: Nivel 0_NPT
Type - Material: Acero (42)
Pset_DistributionFlowElementCommon - Reference: L=2.51m; sets with these values: 2

# IfcFlowTerminal: ARQ-RE-EX-Ace:L=3.20m, ARQ-RE-EX-Ace:L=3.20m:1866697
In: Nivel 0_NPT
Type - Material: Acero (53)
Pset_DistributionFlowElementCommon - Reference: L=3.20m; sets with these values: 2

# IfcFlowTerminal: ARQ-RE-EX-Ace:L=8.36m, ARQ-RE-EX-Ace:L=8.36m:1707116
In: Nivel 0_NPT
Type - Material: Acero (139)
Pset_DistributionFlowElementCommon - Reference: L=8.36m; sets with these values: 2

# IfcFlowTerminal: Inodoro-Ferrum-Espacio-Deposito:Deposito, Inodoro-Ferrum-Espacio-Deposito:Deposito:1924146
In: Nivel 0_NPT
Type - Material: Ceramica - Ferrum - Blanco
Type - Pset_ManufacturerTypeInformation - Manufacturer: Ferrum
Pset_DistributionFlowElementCommon - Reference: Deposito; sets with these values: 2

# IfcFlowTerminal: Inodoro-Ferrum-Espacio-Tapa_y_Asiento:Tapa de Inodoro, Inodoro-Ferrum-Espacio-Tapa_y_Asiento:Tapa de Inodoro:1924147
In: Nivel 0_NPT
Type - Material: Plastico - Ferrum - Urea - Blanco
Type - Pset_ManufacturerTypeInformation - Manufacturer: Ferrum
Pset_DistributionFlowElementCommon - Reference: Tapa de Inodoro; sets with these values: 2

# IfcFlowTerminal: Inodoro-Ferrum-Marina-Deposito:Deposito (4)
In: Nivel 0_NPT
Type - Material: Ceramica - Ferrum - Blanco Satinado, Metal - Ferrum - Cromado
Type - Pset_ManufacturerTypeInformation - Manufacturer: Ferrum
Material: Metal - Ferrum - Cromado, Ceramica - Ferrum - Blanco Satinado
Pset_DistributionFlowElementCommon - Reference: Deposito; sets with these values: 2
Name (Inodoro-Ferrum-Marina-Deposito:Deposito:...)
1817336
1817551
1817783
1817850

# IfcFlowTerminal: Inodoro-Ferrum-Marina-Largo:Inodoro Largo Blanco, Tapa de Urea (4)
In: Nivel 0_NPT
Type - Material: Plastico - Ferrum - Urea - Blanco, Ceramica - Ferrum - Blanco Satinado
Type - Pset_ManufacturerTypeInformation - Manufacturer: Ferrum
Material: Ceramica - Ferrum - Blanco Satinado
Pset_DistributionFlowElementCommon - Reference: Inodoro Largo Blanco, Tapa de Urea; sets with these values: 2
Name (Inodoro-Ferrum-Marina-Largo:Inodoro Largo Blanco, Tapa de Urea:...)
1817335
1817550
1817782
1817849

# IfcFlowTerminal: Inodoro-Ferrum-Marina-Tapa_y_Asiento:Tapa de Inodoro (4)
In: Nivel 0_NPT
Type - Material: Plastico - Ferrum - Urea - Blanco
Type - Pset_ManufacturerTypeInformation - Manufacturer: Ferrum
Pset_DistributionFlowElementCommon - Reference: Tapa de Inodoro; sets with these values: 2
Name (Inodoro-Ferrum-Marina-Tapa_y_Asiento:Tapa de Inodoro:...)
1817337
1817552
1817784
1817851

# IfcFlowTerminal: SAN-BA-IN-Cer:Not a Type - See Type Catalog (6)
In: Nivel 0_NPT
Type - Classification: D2010400 Sinks (Uniformat); Material: Default, Kohler-Metal-CP-Polished_Chrome
Type - Pset_ManufacturerTypeInformation - Manufacturer: KOHLER Co.
Material: Kohler-Metal-CP-Polished_Chrome, Default
Pset_DistributionFlowElementCommon - Reference: Not a Type - See Type Catalog; sets with these values: 2
Name (SAN-BA-IN-Cer:Not a Type - See Type Catalog:...)
1901610
1901740
1901749
1906233
1906282
1906331

# IfcFlowTerminal: SAN-INO-IN-Accesible:Inodoro Corto con Deposito, SAN-INO-IN-Accesible:Inodoro Corto con Deposito:1820061
In: Nivel 0_NPT
Type - Material: Plastico - Ferrum - Urea - Blanco, Ceramica - Ferrum - Blanco
Type - Pset_ManufacturerTypeInformation - Manufacturer: Ferrum
Material: Ceramica - Ferrum - Blanco
Pset_DistributionFlowElementCommon - Reference: Inodoro Corto con Deposito; sets with these values: 2

# IfcFlowTerminal: SAN-LAV-IN-Accesible:Soporte Basculante, SAN-LAV-IN-Accesible:Soporte Basculante:1925662
In: Nivel 0_NPT
Type - Material: Ceramica - Ferrum - Blanco
Type - Pset_ManufacturerTypeInformation - Manufacturer: Ferrum
Pset_DistributionFlowElementCommon - Reference: Soporte Basculante; sets with these values: 2

# IfcFlowTerminal: Sink-Kitchen-KOHLER-Vault-K-3894-4:Under-Mount, NA-Stainless Steel, Sink-Kitchen-KOHLER-Vault-K-3894-4:Under-Mount, NA-Stainless Steel:1913234
In: Nivel 0_NPT
Type - Classification: D2010400 Sinks (Uniformat); Material: Kohler-Metal-NA-Stainless
Type - Pset_ManufacturerTypeInformation - Manufacturer: KOHLER Co.
Pset_DistributionFlowElementCommon - Reference: Under-Mount, NA-Stainless Steel; sets with these values: 2

# IfcFlowTerminal: Urinario:Urinario, Urinario:Urinario:1907284
In: Nivel 0_NPT
Type - Material: Metal - Cromo pulido, Porcelana
Pset_DistributionFlowElementCommon - Reference: Urinario; sets with these values: 2

# IfcFurnishingElement: ARQ-EX-Gradas:ARQ-EX-Gradas, ARQ-EX-Gradas:ARQ-EX-Gradas:1825490
In: Nivel 0_NPT
Type - Material: <Unnamed>, Acero, Hormigón, C20/25
Pset_QuantityTakeOff - Reference: ARQ-EX-Gradas

# IfcFurnishingElement: ARQ-EXT-Pergola-Mad:ARQ-EXT-Pergola-Mad, ARQ-EXT-Pergola-Mad:ARQ-EXT-Pergola-Mad:1827371
In: Nivel 0_NPT
Type - Material: Acero, acabado de pintura, gris oscuro, mate (97)
Pset_QuantityTakeOff - Reference: ARQ-EXT-Pergola-Mad

# IfcFurnishingElement: ARQ-MB-EX-Al:ARQ-MB-EX-Al, ARQ-MB-EX-Al:ARQ-MB-EX-Al:1664283
In: Nivel 0_NPT
Type - Material: Aluminio (42), Acero (4), <Unnamed>
Pset_QuantityTakeOff - Reference: ARQ-MB-EX-Al

# IfcFurnishingElement: ARQ-MB-EX-Butaca:ARQ-MB-EX-Butaca (47)
In: Nivel 0_NPT
Type - Material: Plástico, amarillo
Pset_QuantityTakeOff - Reference: ARQ-MB-EX-Butaca
Name (ARQ-MB-EX-Butaca:ARQ-MB-EX-Butaca:...) | Group
1841382 | Grupo de modelo:Grupo de matriz 1:1841646
1841649 | Grupo de modelo:Grupo de matriz 1:1841650
1841669 | Grupo de modelo:Grupo de matriz 1:1841670
1841672 | Grupo de modelo:Grupo de matriz 1:1841673
1841675 | Grupo de modelo:Grupo de matriz 1:1841676
1841678 | Grupo de modelo:Grupo de matriz 1:1841679
1841681 | Grupo de modelo:Grupo de matriz 1:1841682
1841684 | Grupo de modelo:Grupo de matriz 2:1841895
1841698 | Grupo de modelo:Grupo de matriz 3:1841941
1841735 | Grupo de modelo:Grupo de matriz 4:1842045
1841743 | Grupo de modelo:Grupo de matriz 7:1842224
1841774 | Grupo de modelo:Grupo de matriz 8:1842267
1841782 | Grupo de modelo:Grupo de matriz 5:1842092
1841802 | Grupo de modelo:Grupo de matriz 9:1842298
1841898 | Grupo de modelo:Grupo de matriz 2:1841899
1841917 | Grupo de modelo:Grupo de matriz 2:1841918
1841920 | Grupo de modelo:Grupo de matriz 2:1841921
1841923 | Grupo de modelo:Grupo de matriz 2:1841924
1841926 | Grupo de modelo:Grupo de matriz 2:1841927
1841929 | Grupo de modelo:Grupo de matriz 2:1841930
1841944 | Grupo de modelo:Grupo de matriz 3:1841945
1841960 | Grupo de modelo:Grupo de matriz 3:1841961
1841963 | Grupo de modelo:Grupo de matriz 3:1841964
1841966 | Grupo de modelo:Grupo de matriz 3:1841967
1841969 | Grupo de modelo:Grupo de matriz 3:1841970
1841972 | Grupo de modelo:Grupo de matriz 3:1841973
1841976 | Grupo de modelo:Grupo de matriz 3:1841977
1841979 | Grupo de modelo:Grupo de matriz 3:1841980
1842048 | Grupo de modelo:Grupo de matriz 4:1842049
1842061 | Grupo de modelo:Grupo de matriz 4:1842062
1842064 | Grupo de modelo:Grupo de matriz 4:1842065
1842095 | Grupo de modelo:Grupo de matriz 5:1842096
1842108 | Grupo de modelo:Grupo de matriz 5:1842109
1842111 | Grupo de modelo:Grupo de matriz 5:1842112
1842146 | Grupo de modelo:Grupo de matriz 6:1842185
1842188 | Grupo de modelo:Grupo de matriz 6:1842189
1842206 | Grupo de modelo:Grupo de matriz 6:1842207
1842209 | Grupo de modelo:Grupo de matriz 6:1842210
1842227 | Grupo de modelo:Grupo de matriz 7:1842228
1842245 | Grupo de modelo:Grupo de matriz 7:1842246
1842248 | Grupo de modelo:Grupo de matriz 7:1842249
1842270 | Grupo de modelo:Grupo de matriz 8:1842271
1842284 | Grupo de modelo:Grupo de matriz 8:1842285
1842287 | Grupo de modelo:Grupo de matriz 8:1842288
1842301 | Grupo de modelo:Grupo de matriz 9:1842302
1842316 | Grupo de modelo:Grupo de matriz 9:1842317
1842319 | Grupo de modelo:Grupo de matriz 9:1842320

# IfcFurnishingElement: ARQ-MB-IN-Mad-Me2:ARQ-MB-IN-Mad-Me, ARQ-MB-IN-Mad-Me2:ARQ-MB-IN-Mad-Me:1677025
In: Nivel 0_NPT
Type - Material: Caoba (2), <Unnamed> (2), Acero (2)
Pset_QuantityTakeOff - Reference: ARQ-MB-IN-Mad-Me

# IfcFurnishingElement: ARQ-MB-IN-Mad-Me3:ARQ-MB-IN-Mad-Me, ARQ-MB-IN-Mad-Me3:ARQ-MB-IN-Mad-Me:1682593
In: Nivel 0_NPT
Type - Material: Caoba (4), <Unnamed> (2), Acero (2)
Pset_QuantityTakeOff - Reference: ARQ-MB-IN-Mad-Me

# IfcFurnishingElement: ARQ-MB-IN-Mad-Me:ARQ-MB-IN-141x210-Mad-Me4, ARQ-MB-IN-Mad-Me:ARQ-MB-IN-141x210-Mad-Me4:1673096
In: Nivel 0_NPT
Type - Material: Caoba (4), <Unnamed> (2), Acero (2)
Pset_QuantityTakeOff - Reference: ARQ-MB-IN-141x210-Mad-Me4

# IfcFurnishingElement: ARQ-MB-IN-Mad-Me:ARQ-MB-IN-152x220-Mad-Me1, ARQ-MB-IN-Mad-Me:ARQ-MB-IN-152x220-Mad-Me1:1669636
In: Nivel 0_NPT
Type - Material: Caoba (4), <Unnamed> (2), Acero (2)
Pset_QuantityTakeOff - Reference: ARQ-MB-IN-152x220-Mad-Me1

# IfcFurnishingElement: ARQ-MB-IN-Mesada Baño 1:2 x 0.5m, ARQ-MB-IN-Mesada Baño 1:2 x 0.5m:1904821
In: Nivel 0_NPT
Type - Material: Muro por defecto
Material: Muro por defecto, Encimera de cuarzo, blanco, Espejo
Pset_QuantityTakeOff - Reference: 2 x 0.5m

# IfcFurnishingElement: ARQ-MB-IN-Mesada Baño 1:ARQ-MB-IN-Mesada Baño 1, ARQ-MB-IN-Mesada Baño 1:ARQ-MB-IN-Mesada Baño 1:1896364
In: Nivel 0_NPT
Type - Material: Muro por defecto
Material: Muro por defecto, Encimera de cuarzo, blanco, Espejo
Pset_QuantityTakeOff - Reference: ARQ-MB-IN-Mesada Baño 1

# IfcFurnishingElement: ARQ-MB-IN-Mesada cocina:ARQ-MB-IN-Mesada cocina, ARQ-MB-IN-Mesada cocina:ARQ-MB-IN-Mesada cocina:1908472
In: Nivel 0_NPT
Type - Material: <Unnamed>, Encimera de cuarzo, blanco
Pset_QuantityTakeOff - Reference: ARQ-MB-IN-Mesada cocina

# IfcFurnishingElement: ARQ-MB-IN-YesoMad-Me6:ARQ-MB-IN-YesoMad-Me6, ARQ-MB-IN-YesoMad-Me6:ARQ-MB-IN-YesoMad-Me6:1684918
In: Nivel 0_NPT
Type - Material: Acero (12), Placa de yeso laminado, Caoba (2)
Pset_QuantityTakeOff - Reference: ARQ-MB-IN-YesoMad-Me6

# IfcMember: IPN - Secciones en I con alas cónicas:IPN 160 (4)
In: Nivel 3_SUP
Type - PredefinedType: BRACE; Material: Metal - Acero - 345 MPa
Type - Pset_MemberCommon - IsExternal: no; LoadBearing: yes
Pset_MemberCommon - Reference: IPN 160; Slope: 0 deg; Span: 2.35 m
Pset_QuantityTakeOff - Reference: IPN 160
Name (IPN - Secciones en I con alas cónicas:IPN 160:...)
1306597
1435530
1435561
1435592

# IfcMember: Montante rectangular:10x10 (10)
In: Nivel 0_NPT
Type - PredefinedType: MULLION; Material: Aluminio
Type - Pset_MemberCommon - IsExternal: no
Pset_MemberCommon - Reference: 10x10
Pset_QuantityTakeOff - Reference: 10x10
Name (Montante rectangular:10x10:...) | Span (m)
1632911 | 2.1
1639209 | 2.1
1639522 | 2.125
1639662 | 0.475
1935078 | 2.125
1935080 | 0.475
1644089 | 2.15
1646404 | 2.25
1646842 | 2.25
1648921 | 2.25

# IfcMember: Montante rectangular:3x3 (34)
In: Nivel 0_NPT
Type - PredefinedType: MULLION; Material: Aluminio
Type - Pset_MemberCommon - IsExternal: no
Pset_MemberCommon - Reference: 3x3
Pset_QuantityTakeOff - Reference: 3x3
Name (Montante rectangular:3x3:...) | Span (m)
1783869 | 0.547625
1783871 | 0.592242
1783872 | 0.173524
1783874 | 0.204067
1785912 | 0.203524
1785914 | 0.204067
1785916 | 0.173524
1785920 | 0.562242
1785923 | 0.562242
1933573 | 0.204067
1934006 | 0.592242
1934007 | 0.592242
1934008 | 0.562498
1934009 | 0.57737
1934010 | 0.158524
1934011 | 0.158524
1934012 | 0.173524
1934690 | 0.50705
1934691 | 0.50705
1934692 | 0.163506
1934693 | 0.163506
1934698 | 0.193506
1934699 | 0.193506
1934700 | 0.163506
1934701 | 0.47705
1934702 | 0.47705
1934703 | 0.163506
1934717 | 0.50705
1934718 | 0.50705
1934719 | 0.47705
1934720 | 0.47705
1934721 | 0.148506
1934722 | 0.148506
1934723 | 0.163506

# IfcMember: Montante rectangular:5x10 (12)
In: Nivel 0_NPT
Type - PredefinedType: MULLION; Material: Aluminio
Type - Pset_MemberCommon - IsExternal: no
Pset_MemberCommon - Reference: 5x10
Pset_QuantityTakeOff - Reference: 5x10
Name (Montante rectangular:5x10:...) | Span (m)
1632725 | 0.65
1632907 | 0.75
1639663 | 2.17092
1639664 | 1.005
1935074 | 0.965918
1644069 | 0.466768
1644070 | 0.9
1646843 | 0.9
1646845 | 0.55
1647722 | 1.464
1648685 | 0.9
1648686 | 2.294

# IfcMember: Montante rectangular:5x5 (20)
In: Nivel 0_NPT
Type - PredefinedType: MULLION; Material: Aluminio
Type - Pset_MemberCommon - IsExternal: no
Pset_MemberCommon - Reference: 5x5
Pset_QuantityTakeOff - Reference: 5x5
Name (Montante rectangular:5x5:...) | Span (m)
1817920 | 0.32
1817921 | 1.78
1817929 | 1.78
1817930 | 0.32
1818642 | 0.32
1818643 | 1.78
1818646 | 1.78
1818647 | 0.32
1818676 | 0.32
1818677 | 1.78
1818680 | 1.78
1818681 | 0.32
1818693 | 0.32
1818694 | 1.78
1818697 | 1.78
1818698 | 0.32
1926065 | 0.5
1926066 | 0.5
1926067 | 2.1
1926068 | 2.1

# IfcOpeningElement: Opening (105)
Name | In | Reference | sets with these values
2 x Muro básico:ARQ-MU-EX-15-Gen:445781 | Nivel 0_NPT | ARQ-MU-EX-15-Gen | 2
Muro básico:ARQ-MU-EX-20-Gen:1186663 | Nivel 0_NPT | ARQ-MC-EX-Mampara M4 | 2
2 x Muro básico:ARQ-MU-EX-60-Lad:1552676 | Nivel 0_NPT | ARQ-MU-EX-60-Lad | 2
Muro básico:ARQ-MU-EX-68-Lad:1187422 | Nivel 0_NPT | Mocheta ventana | 2
Muro básico:ARQ-MU-EX-68-Lad:1316325 | Nivel 0_NPT | ARQ-MU-EX-68-Lad | 2
Muro básico:ARQ-MU-EX-60-Lad:1187466 | Nivel 0_NPT | Muros 2 | 2
ARQ-Rejilla ventilación:ARQ-Rejilla ventilación:1970002:1 | Nivel 1_NPT
Muro básico:ARQ-MU-EX-60-Lad:1187466 | Nivel 0_NPT | Muros 1 | 2
Muro básico:ARQ-MU-EX-42-Gen:1553032 | Nivel 0_NPT | ARQ-MU-EX-42-Gen | 2
Muro básico:ARQ-MU-IN-68-Gen:1188952 | Nivel 0_NPT | ARQ-PU-INT-90x210-Mad | 2
3 x Muro básico:ARQ-MU-IN-68-Gen:1316384 | Nivel 0_NPT | ARQ-MU-IN-68-Gen | 2
Muro básico:ARQ-MU-IN-18-Gen:1317478 | Nivel 0_NPT | ARQ-MU-IN-18-Gen | 2
Muro básico:ARQ-MU-IN-16-Gen:1316636 | Nivel 0_NPT | ARQ-MU-IN-16-Gen | 2
Muro básico:ARQ-MU-IN-16-Gen:1192914:1 | Nivel 0_NPT | ARQ-MU-IN-16-Gen | 2
Suelo:ARQ-SU-18 HoA:1262182:2 | Nivel 0_NPT | ARQ-SU-18 HoA | 2
Suelo:ARQ-SU-2-Cer:1263905:2 | Nivel 0_NPT | ARQ-SU-2-Cer | 2
Muro básico:ARQ-MU-EX-36-Gen:1316089 | Nivel 0_NPT | ARQ-PU-INT-65x210-Mad | 2
ARQ-Rejilla ventilación:ARQ-Rejilla ventilación:1970458:1 | Nivel 1_NPT
Muro básico:ARQ-MU-EX-58-Lad:1492961 | Nivel 0_NPT | Muros 2 | 2
Muro básico:ARQ-MU-EX-58-Lad:1492961 | Nivel 0_NPT | Muros 1 | 2
Muro básico:ARQ-MU-IN-13-Ye-T4:1577512 | Nivel 0_NPT | ARQ-MC-IN-Mampara Ma3 | 2
Muro básico:ARQ-MU-IN-9-Ye-T2:1561799 | Nivel 0_NPT | ARQ-MU-IN-9-Ye-T2 | 2
Muro básico:ARQ-MU-IN-16-Ye-T1:1579135 | Nivel 0_NPT | ARQ-MC-IN-Mampara Ma2 | 2
Muro básico:ARQ-MU-IN-16-Ye-T1:1579135 | Nivel 0_NPT | ARQ-MC-IN-Mampara Ma1 | 2
ARQ-PU-INT-90x210-Mad-C3:ARQ-PU-INT-95x210-Mad:1936734:1 | Entrepiso_NPT
Muro básico:ARQ-MU-IN-22-Ye-T5:1582283 | Nivel 0_NPT | ARQ-MC-IN-Mampara Ma4 | 2
Muro básico:ARQ-RE-IN-10-Ye-M6:1585879 | Nivel 0_NPT | ARQ-PU-INT-65x210-Mad | 2
9 x Muro básico:ARQ-RE-IN-5-Ye-M2:1582662 | Nivel 0_NPT | ARQ-RE-IN-5-Ye-M2 | 2
3 x Muro básico:ARQ-RE-IN-2-Ye-M4:1589417 | Nivel 0_NPT | ARQ-RE-IN-2-Ye-M4 | 2
Muro básico:ARQ-RE-IN-2-Ye-M4:1592009 | Nivel 0_NPT | ARQ-PU-INT-90x210-Mad | 2
ARQ-Rejilla ventilación:ARQ-Rejilla ventilación:1966097:1 | Nivel 1_NPT
Muro básico:ARQ-MU-IN-10-Ye-T6:1638342 | Nivel 0_NPT | ARQ-MC-IN-Mampara Ma5 | 2
ARQ-VE-EX-Rejilla:182x81:1710991:1 | Nivel 0_NPT
ARQ-VE-EX-Rejilla:182x111:1712100:1 | Nivel 0_NPT
ARQ-Rejilla ventilación:ARQ-Rejilla ventilación:1964767:1 | Nivel 0_NPT
ARQ-PU-IN-Barra accesible:210x90 cm:1809539:1 | Nivel 0_NPT
ARQ-PU-INT-90x210-Mad-C3:ARQ-PU-INT-90x210-Mad:1661131:1 | Nivel 0_NPT
Suelo:ARQ-SU-EX-2-HormLis:1689621:2 | Nivel 0_NPT | ARQ-SU-EX-2-HormLis | 2
Suelo:ARQ-SU-EX-2-HormLis:1689621:3 | Nivel 0_NPT | ARQ-SU-EX-2-HormLis | 2
Suelo:ARQ-SU-EX-2-HormLis:1689621:4 | Nivel 0_NPT | ARQ-SU-EX-2-HormLis | 2
Suelo:ARQ-SU-EX-2-HormLis:1689621:5 | Nivel 0_NPT | ARQ-SU-EX-2-HormLis | 2
Suelo:ARQ-SU-EX-2-HormLis:1689621:6 | Nivel 0_NPT | ARQ-SU-EX-2-HormLis | 2
Suelo:ARQ-SU-EX-2-HormLis:1689621:7 | Nivel 0_NPT | ARQ-SU-EX-2-HormLis | 2
Suelo:ARQ-SU-EX-2-HormLis:1689621:8 | Nivel 0_NPT | ARQ-SU-EX-2-HormLis | 2
Suelo:ARQ-SU-EX-2-HormLis:1689621:9 | Nivel 0_NPT | ARQ-SU-EX-2-HormLis | 2
Suelo:ARQ-SU-EX-2-HormLis:1689621:10 | Nivel 0_NPT | ARQ-SU-EX-2-HormLis | 2
ARQ-PU-EX-181x260-Alu-A3:ARQ-PU-EX-181x260-Alu-A3:1625602:1 | Nivel 0_NPT
ARQ-VE-EX-234x165-Al-A4:ARQ-VE-EX-224x165-Al-A4:1630412:1 | Nivel 0_NPT
Muro básico:ARQ-MU-IN-18-Gen:1781150 | Nivel 1_NPT | ARQ-Rejilla ventilación | 2
ARQ-PU-EX-80X260-Alu-A2:ARQ-PU-EX-80X260-Alu-A2:1622680:1 | Nivel 0_NPT
ARQ-VE-EX-315x155-Al-A1:ARQ-VE-EX-315x165-Al-A1:1622523:1 | Nivel 0_NPT
ARQ-VE-EX-215x170-Ace:ARQ-VE-EX-215x170-Ace:1310546:1 | Nivel 0_NPT
ARQ-VE-EX-215x170-Ace:ARQ-VE-EX-215x170-Ace:1310545:1 | Nivel 1_NPT
ARQ-VE-EX-215x170-Ace:ARQ-VE-EX-215x170-Ace:1310544:1 | Nivel 1_NPT
ARQ-VE-EX-215x170-Ace:ARQ-VE-EX-215x170-Ace:1310543:1 | Nivel 0_NPT
ARQ-VE-EX-215x170-Ace:ARQ-VE-EX-215x170-Ace:1310542:1 | Nivel 1_NPT
9 x Muro básico:ARQ-RE-IN-5-Ye-M2:1582662 | Nivel 1_NPT | ARQ-RE-IN-5-Ye-M2 | 2
ARQ-VE-EX-215x170-Ace:ARQ-VE-EX-215x170-Ace:1310245:1 | Nivel 1_NPT
ARQ-VE-EX-215x170-Ace:ARQ-VE-EX-215x170-Ace:1310163:1 | Nivel 1_NPT
ARQ-VE-EX-215x170-Ace:ARQ-VE-EX-215x170-Ace:1309955:1 | Nivel 1_NPT
ARQ-VE-EX-215x170-Ace:ARQ-VE-EX-215x170-Ace:1275159:1 | Nivel 0_NPT
Muro básico:ARQ-RE-IN-2-Cer:1974850 | Nivel 0_NPT | ARQ-PU-INT-90x210-Mad | 2
ARQ-VE-EX-215x170-Ace:ARQ-VE-EX-215x170-Ace:1275158:1 | Nivel 0_NPT
ARQ-PU-INT-90x210-Mad-C2:ARQ-PU-INT-65x210-Mad:1662910:1 | Nivel 0_NPT
ARQ-MAM-EX-490x350-Vid:ARQ-MAM-EX-490x350-Vid:1363135:1 | Nivel 0_NPT
ARQ-VE-EX-215x170-Ace:ARQ-VE-EX-215x170-Ace:1274915:1 | Nivel 0_NPT
ARQ-VE-EX-215x170-Ace:ARQ-VE-EX-215x170-Ace:1274916:1 | Nivel 0_NPT
ARQ-VE-EX-215x170-Ace:ARQ-VE-EX-215x170-Ace:1274917:1 | Nivel 0_NPT
ARQ-VE-EX-215x170-Ace:ARQ-VE-EX-215x170-Ace:1274914:1 | Nivel 0_NPT
ARQ-VE-EX-215x170-Ace:ARQ-VE-EX-215x170-Ace:1550437:1 | Nivel 0_NPT
ARQ-VE-EX-215x170-Ace:ARQ-VE-EX-215x170-Ace:1549977:1 | Nivel 0_NPT
ARQ-VE-EX-215x170-Ace:ARQ-VE-EX-215x170-Ace:1550033:1 | Nivel 0_NPT
ARQ-VE-EX-215x170-Ace:ARQ-VE-EX-215x170-Ace:1550436:1 | Nivel 0_NPT
ARQ-PU-INT-90x210-Mad-C3:ARQ-PU-INT-90x210-Mad:1656004:1 | Nivel 0_NPT
ARQ-PU-INT-90x210-Mad-C3:ARQ-PU-INT-80x210-Mad:1253737:1 | Nivel 0_NPT
ARQ-VE-EX-215x170-Ace:ARQ-VE-EX-215x170-Ace:1274303:1 | Nivel 0_NPT
ARQ-VE-EX-215x170-Ace:ARQ-VE-EX-215x170-Ace:1274403:1 | Nivel 0_NPT
ARQ-VE-EX-215x170-Ace:ARQ-VE-EX-215x170-Ace:1274562:1 | Nivel 0_NPT
ARQ-VE-EX-215x170-Ace:ARQ-VE-EX-215x170-Ace:1274634:1 | Nivel 0_NPT
ARQ-VE-EX-215x170-Ace:ARQ-VE-EX-215x170-Ace:1274718:1 | Nivel 0_NPT
ARQ-VE-EX-215x170-Ace:ARQ-VE-EX-215x170-Ace:1275155:1 | Nivel 0_NPT
ARQ-VE-EX-215x170-Ace:ARQ-VE-EX-215x170-Ace:1275156:1 | Nivel 0_NPT
ARQ-VE-EX-215x170-Ace:ARQ-VE-EX-215x170-Ace:1275157:1 | Nivel 0_NPT

# IfcPlate: ARQ-PA-IN-AluVid-Puerta:ARQ-PA-IN-AluVid-Puerta (5)
In: Nivel 0_NPT
Type - PredefinedType: CURTAIN_PANEL; Material: Aluminio, Vidrio
Type - Pset_PlateCommon - IsExternal: no
Material: Aluminio (3), Vidrio
Pset_PlateCommon - Reference: ARQ-PA-IN-AluVid-Puerta
Pset_QuantityTakeOff - Reference: ARQ-PA-IN-AluVid-Puerta
Name (ARQ-PA-IN-AluVid-Puerta:ARQ-PA-IN-AluVid-Puerta:...)
1632517
1639147
1823562
1646349
1648649

# IfcPlate: ARQ-PA-IN-Vidrio Fijo Laminado :ARQ-PA-IN-Vidrio Fijo Laminado (6)
In: Nivel 0_NPT
Type - PredefinedType: CURTAIN_PANEL; Material: Vidrio laminado, Aluminio
Type - Pset_PlateCommon - IsExternal: no
Pset_PlateCommon - Reference: ARQ-PA-IN-Vidrio Fijo Laminado
Pset_QuantityTakeOff - Reference: ARQ-PA-IN-Vidrio Fijo Laminado
Name (ARQ-PA-IN-Vidrio Fijo Laminado :ARQ-PA-IN-Vidrio Fijo Laminado:...)
1639144
1935053
1644027
1646352
1647682
1648653

# IfcPlate: ARQ-PA-IN-Vidrio Fijo:ARQ-PA-IN-Vidrio Fijo (7)
In: Nivel 0_NPT
Type - PredefinedType: CURTAIN_PANEL; Material: Vidrio, Aluminio
Type - Pset_PlateCommon - IsExternal: no
Pset_PlateCommon - Reference: ARQ-PA-IN-Vidrio Fijo
Pset_QuantityTakeOff - Reference: ARQ-PA-IN-Vidrio Fijo
Name (ARQ-PA-IN-Vidrio Fijo:ARQ-PA-IN-Vidrio Fijo:...)
1632873
1639525
1935054
1644040
1646779
1647693
1648661

# IfcPlate: Panel de sistema:Acristalado Superor (12)
In: Nivel 0_NPT
Type - PredefinedType: CURTAIN_PANEL; Material: Vidrio
Type - Pset_PlateCommon - IsExternal: no
Pset_PlateCommon - Reference: Acristalado Superor
Pset_QuantityTakeOff - Reference: Acristalado Superor
Name (Panel de sistema:Acristalado Superor:...)
1783867
1933993
1785879
1933994
1785883
1933995
1934689
1934714
1934695
1934715
1934697
1934716

# IfcPlate: Panel de sistema:Opaco, Panel de sistema:Opaco:1926063
In: Nivel 0_NPT
Type - PredefinedType: CURTAIN_PANEL; Material: <Unnamed>
Type - Pset_PlateCommon - IsExternal: no
Pset_PlateCommon - Reference: Opaco
Pset_QuantityTakeOff - Reference: Opaco

# IfcRailing: Barandilla:ARQ-BA-IN-118-Hi-Ba1 (4)
In: Nivel 1_NPT
Pset_QuantityTakeOff - Reference: ARQ-BA-IN-118-Hi-Ba1
Pset_RailingCommon - IsExternal: no; Reference: ARQ-BA-IN-118-Hi-Ba1; Height: 1.18 m
Name (Barandilla:ARQ-BA-IN-118-Hi-Ba1:...)
1272869
1470292
1703942
1704076

# IfcRailing: Barandilla:ARQ-BA-IN-118-Hi-Ba2 (2)
In: Nivel 1_NPT
Pset_QuantityTakeOff - Reference: ARQ-BA-IN-118-Hi-Ba2
Pset_RailingCommon - IsExternal: no; Reference: ARQ-BA-IN-118-Hi-Ba2; Height: 1.18 m
Name (Barandilla:ARQ-BA-IN-118-Hi-Ba2:...)
1303244
1939919

# IfcRailing: Barandilla:ARQ-BA-IN-118-Hi-Ba3 (2)
In: Nivel 1_NPT
Pset_QuantityTakeOff - Reference: ARQ-BA-IN-118-Hi-Ba3
Pset_RailingCommon - IsExternal: no; Reference: ARQ-BA-IN-118-Hi-Ba3; Height: 1.18 m
Name (Barandilla:ARQ-BA-IN-118-Hi-Ba3:...)
1265398
1303034

# IfcRailing: Barandilla:ARQ-BA-IN-118-Hi-Ba4, Barandilla:ARQ-BA-IN-118-Hi-Ba4:1303130
In: Nivel 1_NPT
Pset_QuantityTakeOff - Reference: ARQ-BA-IN-118-Hi-Ba4
Pset_RailingCommon - IsExternal: no; Reference: ARQ-BA-IN-118-Hi-Ba4; Height: 1.18 m

# IfcRailing: Barandilla:ARQ-BA-IN-Hi-Escalera (5)
Pset_QuantityTakeOff - Reference: ARQ-BA-IN-Hi-Escalera
Pset_RailingCommon - IsExternal: no; Reference: ARQ-BA-IN-Hi-Escalera; Height: 0.9 m
Name (Barandilla:ARQ-BA-IN-Hi-Escalera:...) | In
1574521 | Nivel 0_NPT
1574525 | Nivel 0_NPT
1574610 | Nivel 1_NPT
1574614 | Nivel 1_NPT
1575125 | Nivel 0_NPT

# IfcRailing: Barandilla:ARQ-BA-IN-HiGal-Varillas (4)
In: Nivel 1_NPT
Material: Hierro, dúctil (5)
Pset_QuantityTakeOff - Reference: ARQ-BA-IN-HiGal-Varillas
Pset_RailingCommon - IsExternal: no; Reference: ARQ-BA-IN-HiGal-Varillas; Height: 1.18 m
Name (Barandilla:ARQ-BA-IN-HiGal-Varillas:...)
1700884
1700950
1704374
1704539

# IfcRailing: Barandilla:ARQ-BA-IN-HiGal-Varillas 2 (2)
In: Nivel 1_NPT
Pset_QuantityTakeOff - Reference: ARQ-BA-IN-HiGal-Varillas 2
Pset_RailingCommon - IsExternal: no; Reference: ARQ-BA-IN-HiGal-Varillas 2; Height: 1.18 m
Name (Barandilla:ARQ-BA-IN-HiGal-Varillas 2:...)
1702862
1704057

# IfcRailing: Barandilla:ARQ-BAR-EX-Hi-Rampa (2)
In: Nivel 0_NPT
Pset_QuantityTakeOff - Reference: ARQ-BAR-EX-Hi-Rampa
Pset_RailingCommon - IsExternal: no; Reference: ARQ-BAR-EX-Hi-Rampa; Height: 0.9 m
Name (Barandilla:ARQ-BAR-EX-Hi-Rampa:...)
1687829
1687833

# IfcRailing: Barandilla:ARQ-BAR-EX-Hi-Rampa 2, Barandilla:ARQ-BAR-EX-Hi-Rampa 2:1743685
In: Nivel 0_NPT
Pset_QuantityTakeOff - Reference: ARQ-BAR-EX-Hi-Rampa 2
Pset_RailingCommon - IsExternal: no; Reference: ARQ-BAR-EX-Hi-Rampa 2; Height: 0.9 m

# IfcRailing: Barandilla:ARQ-BAR-EX-Hi-Rampa 3 (2)
In: Nivel 0_NPT
Pset_QuantityTakeOff - Reference: ARQ-BAR-EX-Hi-Rampa 3
Pset_RailingCommon - IsExternal: no; Reference: ARQ-BAR-EX-Hi-Rampa 3; Height: 0.9 m
Name (Barandilla:ARQ-BAR-EX-Hi-Rampa 3:...)
1741033
1741037

# IfcRailing: Soportes 1:Soportes 1, Soportes 1:Soportes 1:1997924
In: Nivel 0_NPT
Type - Material: Metal - Aluminio
Type - Pset_RailingCommon - IsExternal: no
Pset_QuantityTakeOff - Reference: Soportes 1
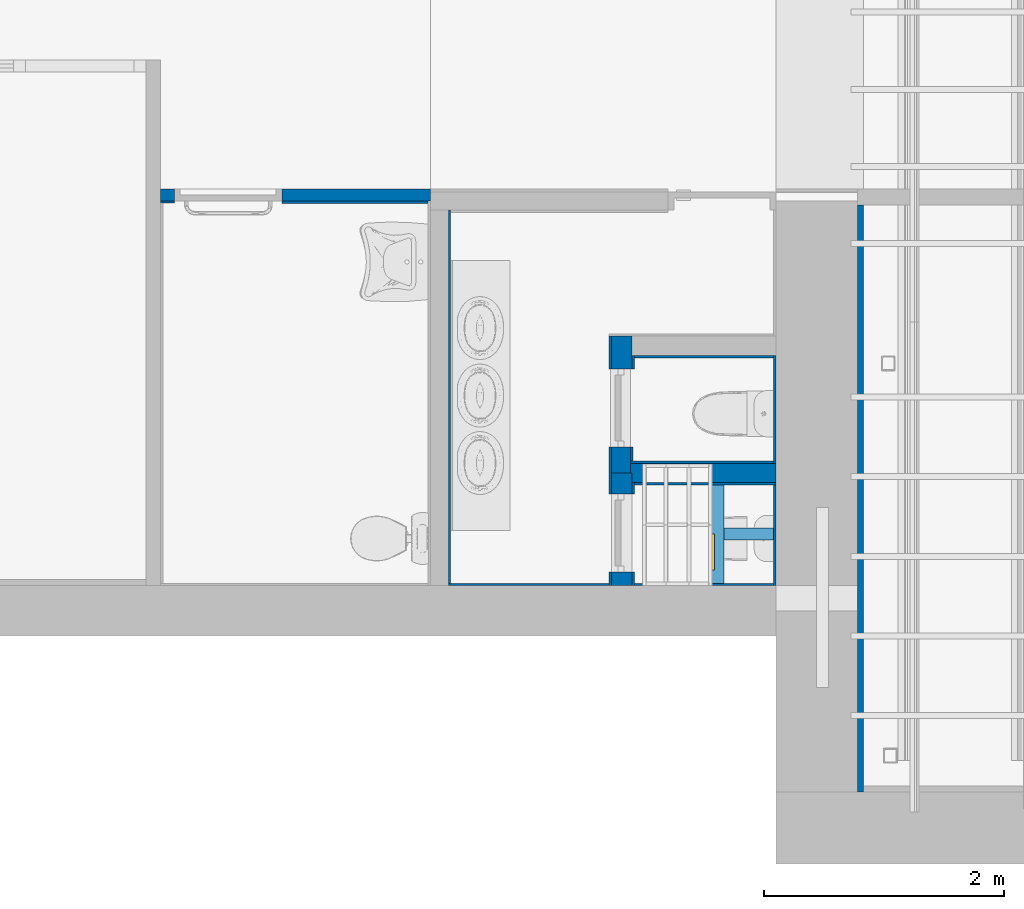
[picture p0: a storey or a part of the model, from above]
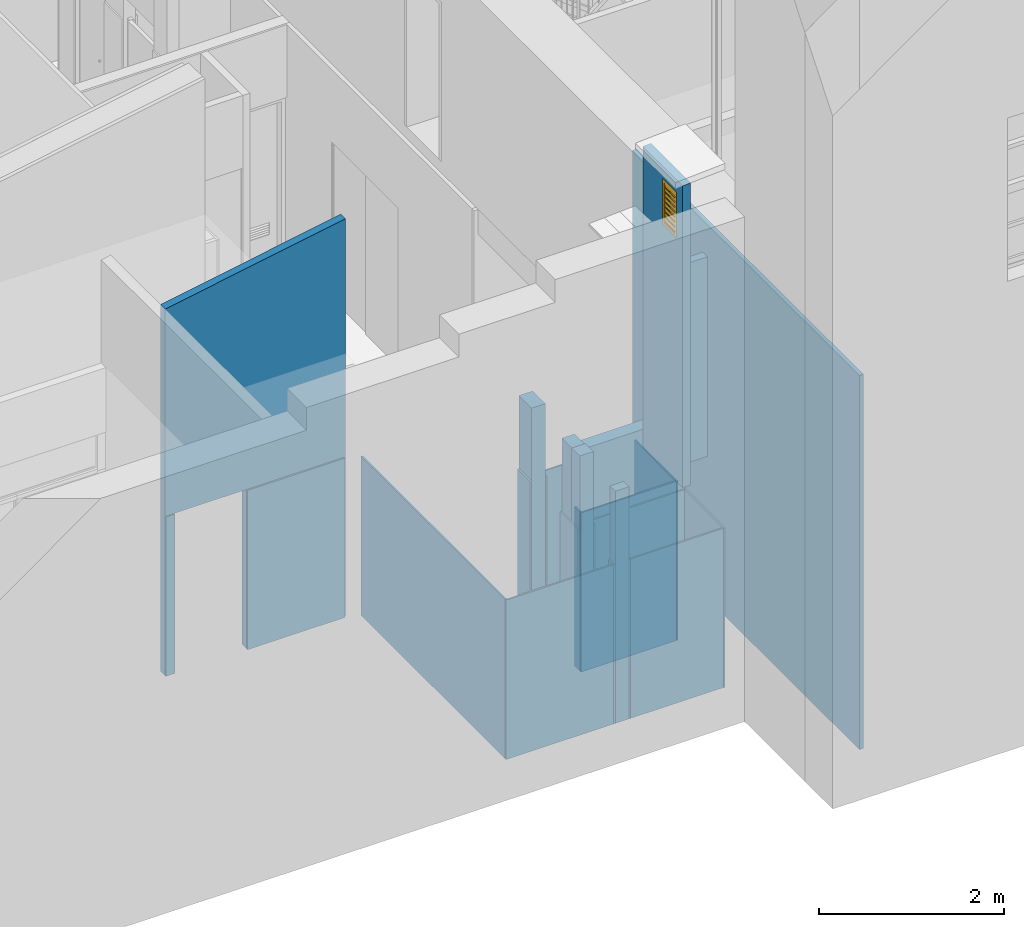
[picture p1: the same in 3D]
Properties of the parts of a building model (IFC2X3), part 2 of 2

# IfcRailing: Soportes 1:Soportes 1, Soportes 1:Soportes 1:1997924
Pset_RailingCommon - Reference: Soportes 1

# IfcRailing: Terminaciones 1:Terminaciones 1, Terminaciones 1:Terminaciones 1:1740871
In: Nivel 0_NPT
Type - Material: Hierro, dúctil
Type - Pset_RailingCommon - IsExternal: no
Pset_QuantityTakeOff - Reference: Terminaciones 1
Pset_RailingCommon - Reference: Terminaciones 1

# IfcRailing: Terminaciones 2:Terminaciones 1, Terminaciones 2:Terminaciones 1:1740942
In: Nivel 0_NPT
Type - Material: Hierro, dúctil
Type - Pset_RailingCommon - IsExternal: no
Pset_QuantityTakeOff - Reference: Terminaciones 1
Pset_RailingCommon - Reference: Terminaciones 1

# IfcRailing: Terminaciones 3:Terminaciones 1, Terminaciones 3:Terminaciones 1:1744154
In: Nivel 0_NPT
Type - Material: Hierro, dúctil
Type - Pset_RailingCommon - IsExternal: no
Pset_QuantityTakeOff - Reference: Terminaciones 1
Pset_RailingCommon - Reference: Terminaciones 1

# IfcRailing: Terminaciones 4:Terminaciones 1, Terminaciones 4:Terminaciones 1:1744271
In: Nivel 0_NPT
Type - Material: Hierro, dúctil
Type - Pset_RailingCommon - IsExternal: no
Pset_QuantityTakeOff - Reference: Terminaciones 1
Pset_RailingCommon - Reference: Terminaciones 1

# IfcRamp: Rampa:Rampa 1 (2)
In: Nivel 0_NPT
Pset_QuantityTakeOff - Reference: Rampa 1
Pset_RampCommon - IsExternal: no; Reference: Rampa 1
Name (Rampa:Rampa 1:...)
1687779
1741014

# IfcRampFlight: Rampa:Rampa 1 (2)
In: Nivel 0_NPT
Material: Hormigón, acabado con escobilla
Pset_QuantityTakeOff - Reference: Rampa 1; sets with these values: 2
Name (Rampa:Rampa 1:...)
1687779:1
1741014:1

# IfcRoof: Cristalera inclinada:ARQ-CA-EX-Lucernario (2)
In: Nivel 0_NPT
Type - Pset_CurtainWallCommon - IsExternal: yes
Pset_QuantityTakeOff - Reference: ARQ-CA-EX-Lucernario
Pset_RoofCommon - IsExternal: yes; Reference: ARQ-CA-EX-Lucernario
Name (Cristalera inclinada:ARQ-CA-EX-Lucernario:...) | ProjectedArea (m2)
1782968 | 0.70832
1934681 | 0.587648

# IfcRoof: Cubierta básica:ARQ-CU-EX-12-Iso (3)
Pset_QuantityTakeOff - Reference: ARQ-CU-EX-12-Iso
Pset_RoofCommon - IsExternal: yes; Reference: ARQ-CU-EX-12-Iso
Name (Cubierta básica:ARQ-CU-EX-12-Iso:...) | In | ProjectedArea (m2) | TotalArea (m2) | Material
1195609 | Nivel 1_NPT | 141.4 | 143.672
1416508 | Nivel 3_SUP | 84.0649 | 96.5548 | Plástico, blanco opaco 0.01 m, EIFS, aislamiento exterior 0.1 m, Plástico, blanco opaco 0.01 m
1436331 | Nivel 3_SUP | 84.0649 | 96.5548 | Plástico, blanco opaco 0.01 m, EIFS, aislamiento exterior 0.1 m, Plástico, blanco opaco 0.01 m

# IfcRoof: Cubierta básica:ARQ-CU-EX-15-Iso, Cubierta básica:ARQ-CU-EX-15-Iso:1196432
In: Nivel 0_NPT
Pset_QuantityTakeOff - Reference: ARQ-CU-EX-15-Iso
Pset_RoofCommon - IsExternal: yes; Reference: ARQ-CU-EX-15-Iso; ProjectedArea: 5.5056 m2; TotalArea: 5.51248 m2

# IfcRoof: Cubierta básica:ARQ-CU-EXT-8-HoA (2)
In: Nivel 0_NPT
Pset_QuantityTakeOff - Reference: ARQ-CU-EXT-8-HoA
Pset_RoofCommon - IsExternal: yes; Reference: ARQ-CU-EXT-8-HoA
Name (Cubierta básica:ARQ-CU-EXT-8-HoA:...) | ProjectedArea (m2) | TotalArea (m2)
1781293 | 0.584225 | 0.585276
1934447 | 0.5332 | 0.534159

# IfcSlab: Cubierta básica:ARQ-CU-EX-12-Iso, Cubierta básica:ARQ-CU-EX-12-Iso:1195609
In: Nivel 1_NPT
Type - PredefinedType: ROOF
Type - Pset_SlabCommon - IsExternal: yes; ThermalTransmittance: 0.226847 kg/K/s3
Material: Plástico, blanco opaco 0.01 m, EIFS, aislamiento exterior 0.1 m, Plástico, blanco opaco 0.01 m
Pset_QuantityTakeOff - Reference: ARQ-CU-EX-12-Iso; sets with these values: 2
Pset_SlabCommon - Reference: ARQ-CU-EX-12-Iso; PitchAngle: 10.204 deg

# IfcSlab: Cubierta básica:ARQ-CU-EX-15-Iso, Cubierta básica:ARQ-CU-EX-15-Iso:1196432
In: Nivel 0_NPT
Type - PredefinedType: ROOF
Type - Pset_SlabCommon - IsExternal: yes; ThermalTransmittance: 0.175052 kg/K/s3
Material: Plástico, blanco opaco 0.01 m, EIFS, aislamiento exterior 0.13 m, Plástico, blanco opaco 0.01 m
Pset_QuantityTakeOff - Reference: ARQ-CU-EX-15-Iso; sets with these values: 2
Pset_SlabCommon - Reference: ARQ-CU-EX-15-Iso; PitchAngle: 2.86241 deg

# IfcSlab: Cubierta básica:ARQ-CU-EXT-8-HoA (2)
In: Nivel 0_NPT
Type - PredefinedType: ROOF
Type - Pset_SlabCommon - IsExternal: yes; ThermalTransmittance: 13.075 kg/K/s3
Material: Hormigón, C20/25 0.08 m
Pset_QuantityTakeOff - Reference: ARQ-CU-EXT-8-HoA; sets with these values: 2
Pset_SlabCommon - Reference: ARQ-CU-EXT-8-HoA; PitchAngle: 3.43363 deg
Name (Cubierta básica:ARQ-CU-EXT-8-HoA:...)
1781293
1934447

# IfcSlab: Suelo:ARQ-SU-13-HoA, Suelo:ARQ-SU-13-HoA:1194356
In: Entrepiso_NPT
Type - PredefinedType: FLOOR; Material: Suelo por defecto 0.13 m
Type - Pset_SlabCommon - IsExternal: no
Pset_QuantityTakeOff - Reference: ARQ-SU-13-HoA; sets with these values: 2
Pset_SlabCommon - LoadBearing: no; Reference: ARQ-SU-13-HoA; PitchAngle: 0 deg

# IfcSlab: Suelo:ARQ-SU-18 HoA (2)
In: Nivel 0_NPT
Type - PredefinedType: FLOOR; Material: Suelo por defecto 0.18 m
Type - Pset_SlabCommon - IsExternal: no
Pset_QuantityTakeOff - Reference: ARQ-SU-18 HoA; sets with these values: 2
Pset_SlabCommon - LoadBearing: no; PitchAngle: 0 deg; Reference: ARQ-SU-18 HoA
Name (Suelo:ARQ-SU-18 HoA:...)
1262182
1741268

# IfcSlab: Suelo:ARQ-SU-2-Cer (3)
Type - PredefinedType: FLOOR; Material: Porcelanato 60x60 0.02 m
Type - Pset_SlabCommon - IsExternal: no
Pset_QuantityTakeOff - Reference: ARQ-SU-2-Cer; sets with these values: 2
Pset_SlabCommon - LoadBearing: no; PitchAngle: 0 deg; Reference: ARQ-SU-2-Cer
Name (Suelo:ARQ-SU-2-Cer:...) | In
1195545 | Entrepiso_NPT
1263905 | Nivel 0_NPT
1265247 | Nivel 0_NPT

# IfcSlab: Suelo:ARQ-SU-20 HoA (2)
In: Nivel 0_NPT
Type - PredefinedType: FLOOR; Material: Suelo por defecto 0.2 m
Type - Pset_SlabCommon - IsExternal: no
Pset_QuantityTakeOff - Reference: ARQ-SU-20 HoA; sets with these values: 2
Pset_SlabCommon - LoadBearing: no; PitchAngle: 0 deg; Reference: ARQ-SU-20 HoA
Name (Suelo:ARQ-SU-20 HoA:...)
1687302:2
1819088

# IfcSlab: Suelo:ARQ-SU-20 HoA, Suelo:ARQ-SU-20 HoA:1687302
In: Nivel 0_NPT
Type - PredefinedType: FLOOR
Type - Pset_SlabCommon - IsExternal: no
Material: Suelo por defecto 0.2 m
Pset_QuantityTakeOff - Reference: ARQ-SU-20 HoA; sets with these values: 2
Pset_SlabCommon - LoadBearing: no; PitchAngle: 0 deg; Reference: ARQ-SU-20 HoA

# IfcSlab: Suelo:ARQ-SU-3-Mad (2)
In: Nivel 1_NPT
Type - PredefinedType: FLOOR; Material: Contrachapado, entablados 0.03 m
Type - Pset_SlabCommon - IsExternal: no; ThermalTransmittance: 3.53333 kg/K/s3
Pset_QuantityTakeOff - Reference: ARQ-SU-3-Mad; sets with these values: 2
Pset_SlabCommon - LoadBearing: no; PitchAngle: 0 deg; Reference: ARQ-SU-3-Mad
Name (Suelo:ARQ-SU-3-Mad:...)
1255340
1701213

# IfcSlab: Suelo:ARQ-SU-EX-2-HormLis, Suelo:ARQ-SU-EX-2-HormLis:1689621
In: Nivel 0_NPT
Type - PredefinedType: FLOOR; Material: Hormigón, Moldeado in situ, gris 0.02 m
Type - Pset_SlabCommon - IsExternal: no; ThermalTransmittance: 52.3 kg/K/s3
Pset_QuantityTakeOff - Reference: ARQ-SU-EX-2-HormLis; sets with these values: 2
Pset_SlabCommon - LoadBearing: no; PitchAngle: 0 deg; Reference: ARQ-SU-EX-2-HormLis

# IfcSlab: Suelo:ARQ-SU-EX-2-HormRay, Suelo:ARQ-SU-EX-2-HormRay:1687932:8
In: Nivel 0_NPT
Type - PredefinedType: FLOOR; Material: Hormigón, acabado con escobilla 0.02 m
Type - Pset_SlabCommon - IsExternal: no; ThermalTransmittance: 52.3 kg/K/s3
Pset_QuantityTakeOff - Reference: ARQ-SU-EX-2-HormRay; sets with these values: 2
Pset_SlabCommon - LoadBearing: no; PitchAngle: 0 deg; Reference: ARQ-SU-EX-2-HormRay

# IfcSlab: Suelo:ARQ-SU-EX-2-HormRay (7)
In: Nivel 0_NPT
Type - PredefinedType: FLOOR
Type - Pset_SlabCommon - IsExternal: no; ThermalTransmittance: 52.3 kg/K/s3
Material: Hormigón, acabado con escobilla 0.02 m
Pset_QuantityTakeOff - Reference: ARQ-SU-EX-2-HormRay; sets with these values: 2
Pset_SlabCommon - LoadBearing: no; PitchAngle: 0 deg; Reference: ARQ-SU-EX-2-HormRay
Name (Suelo:ARQ-SU-EX-2-HormRay:...)
1687932
1687932:2
1687932:3
1687932:4
1687932:5
1687932:6
1687932:7

# IfcSlab: Suelo:ARQ-SU-EX-2.5-Deck, Suelo:ARQ-SU-EX-2.5-Deck:1690839
In: Nivel 0_NPT
Type - PredefinedType: FLOOR; Material: Tablones de madera 0.025 m
Type - Pset_SlabCommon - IsExternal: no; ThermalTransmittance: 7.2 kg/K/s3
Pset_QuantityTakeOff - Reference: ARQ-SU-EX-2.5-Deck; sets with these values: 2
Pset_SlabCommon - LoadBearing: no; PitchAngle: 0 deg; Reference: ARQ-SU-EX-2.5-Deck

# IfcSlab: Suelo:ARQ-SU-EX-2x40x40-BaldHorm (3)
In: Nivel 0_NPT
Type - PredefinedType: FLOOR; Material: Baldosones de hormigón 40x40 0.02 m
Type - Pset_SlabCommon - IsExternal: no
Pset_QuantityTakeOff - Reference: ARQ-SU-EX-2x40x40-BaldHorm; sets with these values: 2
Pset_SlabCommon - LoadBearing: no; PitchAngle: 0 deg; Reference: ARQ-SU-EX-2x40x40-BaldHorm
Name (Suelo:ARQ-SU-EX-2x40x40-BaldHorm:...)
1332493:2
1741296
1818811

# IfcSlab: Suelo:ARQ-SU-EX-2x40x40-BaldHorm, Suelo:ARQ-SU-EX-2x40x40-BaldHorm:1332493
In: Nivel 0_NPT
Type - PredefinedType: FLOOR
Type - Pset_SlabCommon - IsExternal: no
Material: Baldosones de hormigón 40x40 0.02 m
Pset_QuantityTakeOff - Reference: ARQ-SU-EX-2x40x40-BaldHorm; sets with these values: 2
Pset_SlabCommon - LoadBearing: no; PitchAngle: 0 deg; Reference: ARQ-SU-EX-2x40x40-BaldHorm

# IfcStair: Escalera ensamblada:ARQ-ESC-IN-sin vigas (2)
Pset_QuantityTakeOff - Reference: ARQ-ESC-IN-sin vigas
Pset_StairCommon - IsExternal: no; Reference: ARQ-ESC-IN-sin vigas; NumberOfRiser: 25; NumberOfTreads: 24; TreadLength: 0.26 m
Name (Escalera ensamblada:Escalera:...) | In | RiserHeight (m)
1269989 | Nivel 0_NPT | 0.2056
1572165 | Nivel 1_NPT | 0.19

# IfcStairFlight: Tramo no monolítico:Sin contrahuellas (2)
NumberOfRiser: 25; NumberOfTreads: 24; TreadLength: 0.853018 m; Material: Caoba
Pset_QuantityTakeOff - Reference: Sin contrahuellas
Pset_StairFlightCommon - Reference: Sin contrahuellas; NumberOfRiser: 25; NumberOfTreads: 24; TreadLength: 0.26 m; NosingLength: 0 m; TreadLengthAtOffset: 0.26 m; TreadLengthAtInnerSide: 0.26 m
Name (Escalera ensamblada:Escalera:...) | In | RiserHeight (m) | Pset_StairFlightCommon, RiserHeight (m)
1269989 Run 1 | Nivel 0_NPT | 0.674541 | 0.2056
1572165 Run 1 | Nivel 1_NPT | 0.62336 | 0.19

# IfcWall: ARQ-MU-IN-33x33-Gen:ARQ-MU-IN-33x33-Gen, ARQ-MU-IN-33x33-Gen:ARQ-MU-IN-33x33-Gen:1424435
In: Nivel 0_NPT
Type - Material: Muro por defecto
Type - Pset_WallCommon - IsExternal: no
Pset_QuantityTakeOff - Reference: ARQ-MU-IN-33x33-Gen; sets with these values: 2
Pset_WallCommon - Reference: ARQ-MU-IN-33x33-Gen

# IfcWall: Muro básico:ARQ-MU-EX-60-Gen, Muro básico:ARQ-MU-EX-60-Gen:1708997
In: Nivel 0_NPT
Type - PredefinedType: STANDARD; Material: Muro por defecto 0.6 m
Type - Pset_WallCommon - IsExternal: yes
Pset_QuantityTakeOff - Reference: ARQ-MU-EX-60-Gen; sets with these values: 2
Pset_WallCommon - LoadBearing: no; Reference: ARQ-MU-EX-60-Gen; ExtendToStructure: no

# IfcWall: Muro básico:ARQ-MU-EX-68-Lad (3)
Type - PredefinedType: STANDARD; Material: Albañilería expuesta 0.12 m, Muro por defecto 0.56 m
Type - Pset_WallCommon - IsExternal: yes; ThermalTransmittance: 6.75 kg/K/s3
Pset_QuantityTakeOff - Reference: ARQ-MU-EX-68-Lad; sets with these values: 2
Pset_WallCommon - LoadBearing: no; ExtendToStructure: no; Reference: ARQ-MU-EX-68-Lad
Name (Muro básico:ARQ-MU-EX-68-Lad:...) | In
1187519 | Nivel 0_NPT
1309896 | Nivel 1_NPT
1326135 | Nivel 0_NPT

# IfcWall: Muro básico:ARQ-MU-IN-10-Ye-T6, Muro básico:ARQ-MU-IN-10-Ye-T6:1609611
In: Entrepiso_NPT
Type - PredefinedType: STANDARD; Material: Placa yeso entera 0.012 m, Estructura de Hierro Galvanizado 0.073 m, Placa yeso entera 0.015 m
Type - Pset_WallCommon - IsExternal: yes; ThermalTransmittance: 24.0741 kg/K/s3
Pset_QuantityTakeOff - Reference: ARQ-MU-IN-10-Ye-T6; sets with these values: 2
Pset_WallCommon - ExtendToStructure: yes; LoadBearing: no; Reference: ARQ-MU-IN-10-Ye-T6

# IfcWall: Muro básico:ARQ-RE-IN-5-Ye-M2, Muro básico:ARQ-RE-IN-5-Ye-M2:1582851
In: Nivel 0_NPT
Type - PredefinedType: STANDARD; Material: Placa yeso entera 0.012 m, Estructura de Hierro Galvanizado 0.038 m
Type - Pset_WallCommon - IsExternal: yes; ThermalTransmittance: 54.1667 kg/K/s3
Pset_QuantityTakeOff - Reference: ARQ-RE-IN-5-Ye-M2; sets with these values: 2
Pset_WallCommon - LoadBearing: no; ExtendToStructure: no; Reference: ARQ-RE-IN-5-Ye-M2

# IfcWallStandardCase: Muro básico:ARQ-MU-EX-10-Gen (7)
In: Nivel 0_NPT
Type - PredefinedType: STANDARD; Material: Muro por defecto 0.1 m
Type - Pset_WallCommon - IsExternal: yes
Pset_QuantityTakeOff - Reference: ARQ-MU-EX-10-Gen; sets with these values: 2
Pset_WallCommon - LoadBearing: no; ExtendToStructure: no; Reference: ARQ-MU-EX-10-Gen
Name (Muro básico:ARQ-MU-EX-10-Gen:...)
1329136
1329454
1929576
1930332
1931926
1932089
1996306

# IfcWallStandardCase: Muro básico:ARQ-MU-EX-15-Gen, Muro básico:ARQ-MU-EX-15-Gen:1185418
In: Nivel 0_NPT
Type - PredefinedType: STANDARD; Material: Muro por defecto 0.02 m, Muro por defecto 0.13 m
Type - Pset_WallCommon - IsExternal: yes
Pset_QuantityTakeOff - Reference: ARQ-MU-EX-15-Gen; sets with these values: 2
Pset_WallCommon - Reference: ARQ-MU-EX-15-Gen; ExtendToStructure: yes; LoadBearing: no

# IfcWallStandardCase: Muro básico:ARQ-MU-EX-17-Lad, Muro básico:ARQ-MU-EX-17-Lad:1328214
In: Nivel 0_NPT
Type - PredefinedType: STANDARD; Material: Albañilería expuesta 0.17 m
Type - Pset_WallCommon - IsExternal: yes; ThermalTransmittance: 4.76471 kg/K/s3
Pset_QuantityTakeOff - Reference: ARQ-MU-EX-17-Lad; sets with these values: 2
Pset_WallCommon - LoadBearing: no; ExtendToStructure: no; Reference: ARQ-MU-EX-17-Lad

# IfcWallStandardCase: Muro básico:ARQ-MU-EX-20-Gen (2)
In: Nivel 0_NPT
Type - PredefinedType: STANDARD; Material: Muro por defecto 0.02 m, Muro por defecto 0.18 m
Type - Pset_WallCommon - IsExternal: yes
Pset_QuantityTakeOff - Reference: ARQ-MU-EX-20-Gen; sets with these values: 2
Pset_WallCommon - LoadBearing: no; Reference: ARQ-MU-EX-20-Gen
Name (Muro básico:ARQ-MU-EX-20-Gen:...) | ExtendToStructure
1186611 | no
1186663 | yes

# IfcWallStandardCase: Muro básico:ARQ-MU-EX-27-Gen, Muro básico:ARQ-MU-EX-27-Gen:1553423
In: Nivel 0_NPT
Type - PredefinedType: STANDARD; Material: Muro por defecto 0.02 m, Muro por defecto 0.25 m
Type - Pset_WallCommon - IsExternal: yes
Pset_QuantityTakeOff - Reference: ARQ-MU-EX-27-Gen; sets with these values: 2
Pset_WallCommon - LoadBearing: no; ExtendToStructure: no; Reference: ARQ-MU-EX-27-Gen

# IfcWallStandardCase: Muro básico:ARQ-MU-EX-36-Gen, Muro básico:ARQ-MU-EX-36-Gen:1316089
In: Nivel 0_NPT
Type - PredefinedType: STANDARD; Material: Muro por defecto 0.36 m
Type - Pset_WallCommon - IsExternal: yes
Pset_QuantityTakeOff - Reference: ARQ-MU-EX-36-Gen; sets with these values: 2
Pset_WallCommon - ExtendToStructure: yes; LoadBearing: no; Reference: ARQ-MU-EX-36-Gen

# IfcWallStandardCase: Muro básico:ARQ-MU-EX-42-Gen, Muro básico:ARQ-MU-EX-42-Gen:1188584
In: Nivel 0_NPT
Type - PredefinedType: STANDARD; Material: Muro por defecto 0.42 m
Type - Pset_WallCommon - IsExternal: yes
Pset_QuantityTakeOff - Reference: ARQ-MU-EX-42-Gen; sets with these values: 2
Pset_WallCommon - LoadBearing: no; ExtendToStructure: no; Reference: ARQ-MU-EX-42-Gen

# IfcWallStandardCase: Muro básico:ARQ-MU-EX-50-Gen, Muro básico:ARQ-MU-EX-50-Gen:1709612
In: Nivel 0_NPT
Type - PredefinedType: STANDARD; Material: Muro por defecto 0.5 m
Type - Pset_WallCommon - IsExternal: yes
Pset_QuantityTakeOff - Reference: ARQ-MU-EX-50-Gen; sets with these values: 2
Pset_WallCommon - LoadBearing: no; ExtendToStructure: no; Reference: ARQ-MU-EX-50-Gen

# IfcWallStandardCase: Muro básico:ARQ-MU-EX-58-Lad, Muro básico:ARQ-MU-EX-58-Lad:1492961
In: Nivel 0_NPT
Type - PredefinedType: STANDARD; Material: Albañilería expuesta 0.12 m, Muro por defecto 0.46 m
Type - Pset_WallCommon - IsExternal: yes; ThermalTransmittance: 6.75 kg/K/s3
Pset_QuantityTakeOff - Reference: ARQ-MU-EX-58-Lad; sets with these values: 2
Pset_WallCommon - LoadBearing: no; ExtendToStructure: no; Reference: ARQ-MU-EX-58-Lad

# IfcWallStandardCase: Muro básico:ARQ-MU-EX-60-Gen, Muro básico:ARQ-MU-EX-60-Gen:1185739
In: Nivel 0_NPT
Type - PredefinedType: STANDARD; Material: Muro por defecto 0.6 m
Type - Pset_WallCommon - IsExternal: yes
Pset_QuantityTakeOff - Reference: ARQ-MU-EX-60-Gen; sets with these values: 2
Pset_WallCommon - LoadBearing: no; Reference: ARQ-MU-EX-60-Gen; ExtendToStructure: no

# IfcWallStandardCase: Muro básico:ARQ-MU-EX-60-Lad (2)
In: Nivel 0_NPT
Type - PredefinedType: STANDARD; Material: Albañilería expuesta 0.12 m, Muro por defecto 0.48 m
Type - Pset_WallCommon - IsExternal: yes; ThermalTransmittance: 6.75 kg/K/s3
Pset_QuantityTakeOff - Reference: ARQ-MU-EX-60-Lad; sets with these values: 2
Pset_WallCommon - LoadBearing: no; ExtendToStructure: no; Reference: ARQ-MU-EX-60-Lad
Name (Muro básico:ARQ-MU-EX-60-Lad:...)
1187334
1187466

# IfcWallStandardCase: Muro básico:ARQ-MU-EX-68-Lad, Muro básico:ARQ-MU-EX-68-Lad:1187422
In: Nivel 0_NPT
Type - PredefinedType: STANDARD; Material: Albañilería expuesta 0.12 m, Muro por defecto 0.56 m
Type - Pset_WallCommon - IsExternal: yes; ThermalTransmittance: 6.75 kg/K/s3
Pset_QuantityTakeOff - Reference: ARQ-MU-EX-68-Lad; sets with these values: 2
Pset_WallCommon - LoadBearing: no; ExtendToStructure: no; Reference: ARQ-MU-EX-68-Lad

# IfcWallStandardCase: Muro básico:ARQ-MU-IN-10-Ye-T6 (2)
In: Nivel 0_NPT
Type - PredefinedType: STANDARD; Material: Placa yeso entera 0.012 m, Estructura de Hierro Galvanizado 0.073 m, Placa yeso entera 0.015 m
Type - Pset_WallCommon - IsExternal: yes; ThermalTransmittance: 24.0741 kg/K/s3
Pset_QuantityTakeOff - Reference: ARQ-MU-IN-10-Ye-T6; sets with these values: 2
Pset_WallCommon - ExtendToStructure: yes; LoadBearing: no; Reference: ARQ-MU-IN-10-Ye-T6
Name (Muro básico:ARQ-MU-IN-10-Ye-T6:...)
1600552
1638342

# IfcWallStandardCase: Muro básico:ARQ-MU-IN-10-Ye-T8 (6)
Type - PredefinedType: STANDARD; Material: Placa yeso entera 0.015 m, Estructura de Hierro Galvanizado 0.07 m, Placa yeso entera 0.015 m
Type - Pset_WallCommon - IsExternal: yes; ThermalTransmittance: 21.6667 kg/K/s3
Pset_QuantityTakeOff - Reference: ARQ-MU-IN-10-Ye-T8; sets with these values: 2
Pset_WallCommon - LoadBearing: no; Reference: ARQ-MU-IN-10-Ye-T8
Name (Muro básico:ARQ-MU-IN-10-Ye-T8:...) | In | ExtendToStructure
1609806 | Nivel 0_NPT | yes
1609842 | Nivel 0_NPT | no
1610000 | Nivel 0_NPT | no
1784373 | Nivel 1_NPT | yes
1965387 | Nivel 1_NPT | yes
1969954 | Nivel 1_NPT | yes

# IfcWallStandardCase: Muro básico:ARQ-MU-IN-12-Gen, Muro básico:ARQ-MU-IN-12-Gen:1328839
In: Nivel 0_NPT
Type - PredefinedType: STANDARD; Material: Muro por defecto 0.12 m
Type - Pset_WallCommon - IsExternal: yes
Pset_QuantityTakeOff - Reference: ARQ-MU-IN-12-Gen; sets with these values: 2
Pset_WallCommon - LoadBearing: no; ExtendToStructure: no; Reference: ARQ-MU-IN-12-Gen

# IfcWallStandardCase: Muro básico:ARQ-MU-IN-12-Ye-T7, Muro básico:ARQ-MU-IN-12-Ye-T7:1581397
In: Nivel 0_NPT
Type - PredefinedType: STANDARD; Material: Placa yeso entera 0.015 m, Placa yeso entera 0.015 m, Estructura de Hierro Galvanizado 0.07 m, Placa yeso entera 0.02 m
Type - Pset_WallCommon - IsExternal: no; ThermalTransmittance: 13 kg/K/s3
Pset_QuantityTakeOff - Reference: ARQ-MU-IN-12-Ye-T7; sets with these values: 2
Pset_WallCommon - ExtendToStructure: yes; LoadBearing: no; Reference: ARQ-MU-IN-12-Ye-T7

# IfcWallStandardCase: Muro básico:ARQ-MU-IN-13-Ye-T4 (3)
In: Nivel 0_NPT
Type - PredefinedType: STANDARD; Material: Placa yeso entera 0.015 m, Placa yeso entera 0.015 m, Estructura de Hierro Galvanizado 0.07 m, Placa yeso entera 0.015 m, Placa yeso entera 0.015 m
Type - Pset_WallCommon - IsExternal: no; ThermalTransmittance: 10.8333 kg/K/s3
Pset_QuantityTakeOff - Reference: ARQ-MU-IN-13-Ye-T4; sets with these values: 2
Pset_WallCommon - LoadBearing: no; ExtendToStructure: no; Reference: ARQ-MU-IN-13-Ye-T4
Name (Muro básico:ARQ-MU-IN-13-Ye-T4:...)
1577327
1577512
1988244

# IfcWallStandardCase: Muro básico:ARQ-MU-IN-15-Gen (12)
Type - PredefinedType: STANDARD; Material: Muro por defecto 0.15 m
Type - Pset_WallCommon - IsExternal: yes
Pset_QuantityTakeOff - Reference: ARQ-MU-IN-15-Gen; sets with these values: 2
Pset_WallCommon - LoadBearing: no; Reference: ARQ-MU-IN-15-Gen
Name (Muro básico:ARQ-MU-IN-15-Gen:...) | In | ExtendToStructure
1186372 | Nivel 0_NPT | no
1187972 | Nivel 0_NPT | no
1195022 | Entrepiso_NPT | yes
1443090 | Nivel 0_NPT | no
1443153 | Nivel 0_NPT | no
1443260 | Nivel 0_NPT | no
1461452 | Entrepiso_NPT | yes
1552244 | Nivel 0_NPT | no
1581019 | Nivel 0_NPT | no
1590506 | Nivel 0_NPT | no
1916836 | Nivel 0_NPT | no
1916918 | Nivel 0_NPT | no

# IfcWallStandardCase: Muro básico:ARQ-MU-IN-16-Gen (5)
In: Nivel 0_NPT
Type - PredefinedType: STANDARD; Material: Muro por defecto 0.16 m
Type - Pset_WallCommon - IsExternal: yes
Pset_QuantityTakeOff - Reference: ARQ-MU-IN-16-Gen; sets with these values: 2
Pset_WallCommon - LoadBearing: no; ExtendToStructure: no; Reference: ARQ-MU-IN-16-Gen
Name (Muro básico:ARQ-MU-IN-16-Gen:...)
1192375
1192567
1192914
1193069
1193141

# IfcWallStandardCase: Muro básico:ARQ-MU-IN-16-Ye-T1, Muro básico:ARQ-MU-IN-16-Ye-T1:1579135
In: Nivel 0_NPT
Type - PredefinedType: STANDARD; Material: Placa yeso entera 0.015 m, Placa yeso entera 0.015 m, Estructura de Hierro Galvanizado 0.1 m, Placa yeso entera 0.015 m, Placa yeso entera 0.015 m
Type - Pset_WallCommon - IsExternal: no; ThermalTransmittance: 10.8333 kg/K/s3
Pset_QuantityTakeOff - Reference: ARQ-MU-IN-16-Ye-T1; sets with these values: 2
Pset_WallCommon - LoadBearing: no; ExtendToStructure: no; Reference: ARQ-MU-IN-16-Ye-T1

# IfcWallStandardCase: Muro básico:ARQ-MU-IN-17-Gen (6)
In: Nivel 0_NPT
Type - PredefinedType: STANDARD; Material: Muro por defecto 0.17 m
Type - Pset_WallCommon - IsExternal: yes
Pset_QuantityTakeOff - Reference: ARQ-MU-IN-17-Gen; sets with these values: 2
Pset_WallCommon - LoadBearing: no; ExtendToStructure: no; Reference: ARQ-MU-IN-17-Gen
Name (Muro básico:ARQ-MU-IN-17-Gen:...)
1187739
1192783
1317063
1552570
1917310
1917553

# IfcWallStandardCase: Muro básico:ARQ-MU-IN-18-Gen (9)
Type - PredefinedType: STANDARD; Material: Muro por defecto 0.18 m
Type - Pset_WallCommon - IsExternal: yes
Pset_QuantityTakeOff - Reference: ARQ-MU-IN-18-Gen; sets with these values: 2
Pset_WallCommon - LoadBearing: no; Reference: ARQ-MU-IN-18-Gen
Name (Muro básico:ARQ-MU-IN-18-Gen:...) | In | ExtendToStructure
1192245 | Nivel 0_NPT | no
1461016 | Entrepiso_NPT | yes
1461242 | Entrepiso_NPT | yes
1461533 | Entrepiso_NPT | yes
1609974 | Nivel 0_NPT | no
1780750 | Nivel 1_NPT | yes
1781150 | Nivel 1_NPT | yes
1784857 | Entrepiso_NPT | yes
1969617 | Nivel 1_NPT | yes

# IfcWallStandardCase: Muro básico:ARQ-MU-IN-22-Ye-T5, Muro básico:ARQ-MU-IN-22-Ye-T5:1582283
In: Nivel 0_NPT
Type - PredefinedType: STANDARD; Material: Placa yeso entera 0.0125 m, Placa yeso entera 0.0125 m, Estructura de Hierro Galvanizado 0.07 m, Aire 0.03 m, Estructura de Hierro Galvanizado 0.07 m, Placa yeso entera 0.0125 m, Placa yeso entera 0.0125 m
Type - Pset_WallCommon - IsExternal: yes; ThermalTransmittance: 0.783133 kg/K/s3
Pset_QuantityTakeOff - Reference: ARQ-MU-IN-22-Ye-T5; sets with these values: 2
Pset_WallCommon - LoadBearing: no; ExtendToStructure: no; Reference: ARQ-MU-IN-22-Ye-T5

# IfcWallStandardCase: Muro básico:ARQ-MU-IN-30-Gen (2)
In: Nivel 0_NPT
Type - PredefinedType: STANDARD; Material: Muro por defecto 0.3 m
Type - Pset_WallCommon - IsExternal: yes
Pset_QuantityTakeOff - Reference: ARQ-MU-IN-30-Gen; sets with these values: 2
Pset_WallCommon - ExtendToStructure: yes; LoadBearing: no; Reference: ARQ-MU-IN-30-Gen
Name (Muro básico:ARQ-MU-IN-30-Gen:...)
1185622
1822207

# IfcWallStandardCase: Muro básico:ARQ-MU-IN-50-Gen, Muro básico:ARQ-MU-IN-50-Gen:1822316
In: Nivel 0_NPT
Type - PredefinedType: STANDARD; Material: Muro por defecto 0.5 m
Type - Pset_WallCommon - IsExternal: yes
Pset_QuantityTakeOff - Reference: ARQ-MU-IN-50-Gen; sets with these values: 2
Pset_WallCommon - LoadBearing: no; ExtendToStructure: no; Reference: ARQ-MU-IN-50-Gen

# IfcWallStandardCase: Muro básico:ARQ-MU-IN-68-Gen (2)
In: Nivel 0_NPT
Type - PredefinedType: STANDARD; Material: Muro por defecto 0.68 m
Type - Pset_WallCommon - IsExternal: yes
Pset_QuantityTakeOff - Reference: ARQ-MU-IN-68-Gen; sets with these values: 2
Pset_WallCommon - LoadBearing: no; ExtendToStructure: no; Reference: ARQ-MU-IN-68-Gen
Name (Muro básico:ARQ-MU-IN-68-Gen:...)
1188952
1189431

# IfcWallStandardCase: Muro básico:ARQ-MU-IN-8-Ye-T3 (6)
In: Nivel 0_NPT
Type - PredefinedType: STANDARD; Material: Placa yeso entera 0.01 m, Estructura de Hierro Galvanizado 0.07 m
Type - Pset_WallCommon - IsExternal: no; ThermalTransmittance: 65 kg/K/s3
Pset_QuantityTakeOff - Reference: ARQ-MU-IN-8-Ye-T3; sets with these values: 2
Pset_WallCommon - LoadBearing: no; ExtendToStructure: no; Reference: ARQ-MU-IN-8-Ye-T3
Name (Muro básico:ARQ-MU-IN-8-Ye-T3:...)
1578441
1578631
1578854
1587914
1588000
1588400

# IfcWallStandardCase: Muro básico:ARQ-MU-IN-9-Ye-T2 (6)
In: Nivel 0_NPT
Type - PredefinedType: STANDARD; Material: Placa yeso entera 0.01 m, Estructura de Hierro Galvanizado 0.07 m, Placa yeso entera 0.01 m
Type - Pset_WallCommon - IsExternal: no; ThermalTransmittance: 32.5 kg/K/s3
Pset_QuantityTakeOff - Reference: ARQ-MU-IN-9-Ye-T2; sets with these values: 2
Pset_WallCommon - LoadBearing: no; ExtendToStructure: no; Reference: ARQ-MU-IN-9-Ye-T2
Name (Muro básico:ARQ-MU-IN-9-Ye-T2:...)
1578012
1581220
1611087
1679309
1683271
1833248

# IfcWallStandardCase: Muro básico:ARQ-RE-IN-1.4-Cer, Muro básico:ARQ-RE-IN-1.4-Cer:1601855
In: Nivel 0_NPT
Type - PredefinedType: STANDARD; Material: Hormigón, Moldeado in situ, gris 0.005 m, Ceramica - Ferrum - Blanco 0.009 m
Type - Pset_WallCommon - IsExternal: no; ThermalTransmittance: 209.2 kg/K/s3
Pset_QuantityTakeOff - Reference: ARQ-RE-IN-1.4-Cer; sets with these values: 2
Pset_WallCommon - LoadBearing: no; ExtendToStructure: no; Reference: ARQ-RE-IN-1.4-Cer

# IfcWallStandardCase: Muro básico:ARQ-RE-IN-1.5-Ye (4)
In: Nivel 0_NPT
Type - PredefinedType: STANDARD; Material: Placa yeso entera 0.015 m
Type - Pset_WallCommon - IsExternal: yes; ThermalTransmittance: 43.3333 kg/K/s3
Pset_QuantityTakeOff - Reference: ARQ-RE-IN-1.5-Ye; sets with these values: 2
Pset_WallCommon - LoadBearing: no; ExtendToStructure: no; Reference: ARQ-RE-IN-1.5-Ye
Name (Muro básico:ARQ-RE-IN-1.5-Ye:...)
1588807
1588887
1588940
1588989

# IfcWallStandardCase: Muro básico:ARQ-RE-IN-10-Ye-M6 (2)
In: Nivel 0_NPT
Type - PredefinedType: STANDARD; Material: Placa yeso entera 0.015 m, Placa yeso entera 0.015 m, Estructura de Hierro Galvanizado 0.07 m
Type - Pset_WallCommon - IsExternal: yes; ThermalTransmittance: 21.6667 kg/K/s3
Pset_QuantityTakeOff - Reference: ARQ-RE-IN-10-Ye-M6; sets with these values: 2
Pset_WallCommon - ExtendToStructure: yes; LoadBearing: no; Reference: ARQ-RE-IN-10-Ye-M6
Name (Muro básico:ARQ-RE-IN-10-Ye-M6:...)
1585723
1585879

# IfcWallStandardCase: Muro básico:ARQ-RE-IN-2-Cer (48)
In: Nivel 0_NPT
Type - PredefinedType: STANDARD; Material: Hormigón, Moldeado in situ, gris 0.01 m, Ceramica - Ferrum - Blanco 0.01 m
Type - Pset_WallCommon - IsExternal: no; ThermalTransmittance: 104.6 kg/K/s3
Pset_QuantityTakeOff - Reference: ARQ-RE-IN-2-Cer; sets with these values: 2
Pset_WallCommon - LoadBearing: no; ExtendToStructure: no; Reference: ARQ-RE-IN-2-Cer
Name (Muro básico:ARQ-RE-IN-2-Cer:...)
1601344
1601397
1602111
1609289
1801709
1801987
1802107
1813650
1813749
1814003
1814083
1814205
1814374
1823173
1974850
1975056
1975100
1975149
1975268
1975340
1975446
1975533
1975637
1975750
1975830
1975922
1975972
1976024
1976082
1976174
1976374
1976508
1976728
1976800
1976870
1976896
1976964
1977959
1978008
1978218
1978275
1978322
1978410
1978506
1978565
1978605
1978651
1978748

# IfcWallStandardCase: Muro básico:ARQ-RE-IN-2-Ye-M4 (9)
In: Nivel 0_NPT
Type - PredefinedType: STANDARD; Material: Placa yeso entera 0.012 m, Estructura de Hierro Galvanizado 0.013 m
Type - Pset_WallCommon - IsExternal: yes; ThermalTransmittance: 54.1667 kg/K/s3
Pset_QuantityTakeOff - Reference: ARQ-RE-IN-2-Ye-M4; sets with these values: 2
Pset_WallCommon - LoadBearing: no; ExtendToStructure: no; Reference: ARQ-RE-IN-2-Ye-M4
Name (Muro básico:ARQ-RE-IN-2-Ye-M4:...)
1589485
1589986
1591461
1592009
1592678
1592749
1593152
1593511
1802536

# IfcWallStandardCase: Muro básico:ARQ-RE-IN-5-Ye-M2 (24)
Type - PredefinedType: STANDARD; Material: Placa yeso entera 0.012 m, Estructura de Hierro Galvanizado 0.038 m
Type - Pset_WallCommon - IsExternal: yes; ThermalTransmittance: 54.1667 kg/K/s3
Pset_QuantityTakeOff - Reference: ARQ-RE-IN-5-Ye-M2; sets with these values: 2
Pset_WallCommon - LoadBearing: no; Reference: ARQ-RE-IN-5-Ye-M2
Name (Muro básico:ARQ-RE-IN-5-Ye-M2:...) | In | ExtendToStructure
1583648 | Nivel 0_NPT | yes
1583723 | Nivel 0_NPT | no
1583942 | Nivel 0_NPT | yes
1584011 | Nivel 0_NPT | yes
1584115 | Nivel 0_NPT | yes
1584180 | Nivel 0_NPT | yes
1584307 | Nivel 0_NPT | no
1584924 | Nivel 0_NPT | yes
1585233 | Nivel 0_NPT | yes
1585320 | Nivel 0_NPT | yes
1586260 | Nivel 0_NPT | no
1586447 | Nivel 0_NPT | no
1586655 | Nivel 0_NPT | no
1586761 | Nivel 0_NPT | no
1587026 | Nivel 0_NPT | no
1587233 | Nivel 0_NPT | no
1587349 | Nivel 0_NPT | no
1587615 | Nivel 0_NPT | no
1587760 | Nivel 0_NPT | no
1605745 | Entrepiso_NPT | yes
1609398 | Nivel 0_NPT | no
1802271 | Nivel 0_NPT | no
1926832 | Nivel 1_NPT | no
1927128 | Nivel 1_NPT | no

# IfcWindow: ARQ-Rejilla ventilación:ARQ-Rejilla ventilación (4)
In: Nivel 1_NPT
Type - ParameterTakesPrecedence: no; Sizeable: no; Material: Aluminio (1) (10)
Type - Pset_WindowCommon - IsExternal: no
OverallHeight: 0.6 m; OverallWidth: 0.3 m
Pset_QuantityTakeOff - Reference: ARQ-Rejilla ventilación
Pset_WindowCommon - Reference: ARQ-Rejilla ventilación
Name (ARQ-Rejilla ventilación:ARQ-Rejilla ventilación:...)
1964767 | Pset_WindowCommon - IsExternal: yes
1966097
1970002 | Material: Aluminio (1)
1970458 | Material: Aluminio (1)

# IfcWindow: ARQ-VE-EX-215x170-Ace:ARQ-VE-EX-215x170-Ace (26)
Type - ParameterTakesPrecedence: no; Sizeable: no; Material: Nogal (3), Vidrio (8)
Type - Pset_WindowCommon - IsExternal: no
OverallHeight: 2.15 m; OverallWidth: 1.5 m
Pset_QuantityTakeOff - Reference: ARQ-VE-EX-215x170-Ace
Pset_WindowCommon - Reference: ARQ-VE-EX-215x170-Ace
Name (ARQ-VE-EX-215x170-Ace:ARQ-VE-EX-215x170-Ace:...) | In | Material
1274303 | Nivel 1_NPT | Pset_WindowCommon - IsExternal: yes
1274403 | Nivel 1_NPT
1274562 | Nivel 1_NPT | Nogal, Vidrio
1274634 | Nivel 1_NPT | Nogal, Vidrio
1274718 | Nivel 1_NPT | Nogal, Vidrio
1274914 | Nivel 0_NPT
1274915 | Nivel 0_NPT
1274916 | Nivel 0_NPT | Nogal, Vidrio
1274917 | Nivel 0_NPT | Nogal, Vidrio
1275155 | Nivel 1_NPT | Nogal, Vidrio
1275156 | Nivel 1_NPT | Nogal, Vidrio
1275157 | Nivel 1_NPT | Nogal, Vidrio
1275158 | Nivel 1_NPT | Nogal, Vidrio
1275159 | Nivel 1_NPT | Nogal, Vidrio
1309955 | Nivel 1_NPT | Nogal, Vidrio
1310163 | Nivel 1_NPT | Nogal, Vidrio
1310245 | Nivel 1_NPT | Nogal, Vidrio
1310542 | Nivel 1_NPT | Nogal, Vidrio
1310543 | Nivel 1_NPT | Nogal, Vidrio
1310544 | Nivel 1_NPT | Nogal, Vidrio
1310545 | Nivel 1_NPT | Nogal, Vidrio
1310546 | Nivel 1_NPT | Nogal, Vidrio
1549977 | Nivel 1_NPT
1550033 | Nivel 1_NPT | Nogal, Vidrio
1550436 | Nivel 1_NPT | Nogal, Vidrio
1550437 | Nivel 1_NPT | Nogal, Vidrio

# IfcWindow: ARQ-VE-EX-234x165-Al-A4:ARQ-VE-EX-224x165-Al-A4, ARQ-VE-EX-234x165-Al-A4:ARQ-VE-EX-224x165-Al-A4:1630412
In: Nivel 0_NPT
Type - ParameterTakesPrecedence: no; Sizeable: no; Material: Hormigón, prefabricado, Vidrio (4), Aluminio (10)
Type - Pset_WindowCommon - IsExternal: no
OverallHeight: 1.72 m; OverallWidth: 2.24 m
Pset_QuantityTakeOff - Reference: ARQ-VE-EX-224x165-Al-A4
Pset_WindowCommon - IsExternal: yes; Reference: ARQ-VE-EX-224x165-Al-A4

# IfcWindow: ARQ-VE-EX-315x155-Al-A1:ARQ-VE-EX-315x165-Al-A1, ARQ-VE-EX-315x155-Al-A1:ARQ-VE-EX-315x165-Al-A1:1622523
In: Nivel 0_NPT
Type - ParameterTakesPrecedence: no; Sizeable: no; Material: Vidrio (8), Aluminio (21), Hormigón, prefabricado
Type - Pset_WindowCommon - IsExternal: no
OverallHeight: 1.72 m; OverallWidth: 3.15 m
Pset_QuantityTakeOff - Reference: ARQ-VE-EX-315x165-Al-A1
Pset_WindowCommon - IsExternal: yes; Reference: ARQ-VE-EX-315x165-Al-A1

# IfcWindow: ARQ-VE-EX-Rejilla:182x111, ARQ-VE-EX-Rejilla:182x111:1712100
In: Nivel 0_NPT
Type - ParameterTakesPrecedence: no; Sizeable: no; Material: Revestimiento de metal (4), Acero (6)
Type - Pset_WindowCommon - IsExternal: no
OverallHeight: 1.11 m; OverallWidth: 1.82 m
Pset_QuantityTakeOff - Reference: 182x111
Pset_WindowCommon - IsExternal: yes; Reference: 182x111

# IfcWindow: ARQ-VE-EX-Rejilla:182x81, ARQ-VE-EX-Rejilla:182x81:1710991
In: Nivel 0_NPT
Type - ParameterTakesPrecedence: no; Sizeable: no; Material: Revestimiento de metal (4), Acero (6)
Type - Pset_WindowCommon - IsExternal: no
OverallHeight: 0.81 m; OverallWidth: 1.82 m
Pset_QuantityTakeOff - Reference: 182x81
Pset_WindowCommon - IsExternal: yes; Reference: 182x81
